VERSION 5.8 ;
BUSBITCHARS "[]" ;
DIVIDERCHAR "/" ;
UNITS
    DATABASE MICRONS 1000 ;
END UNITS

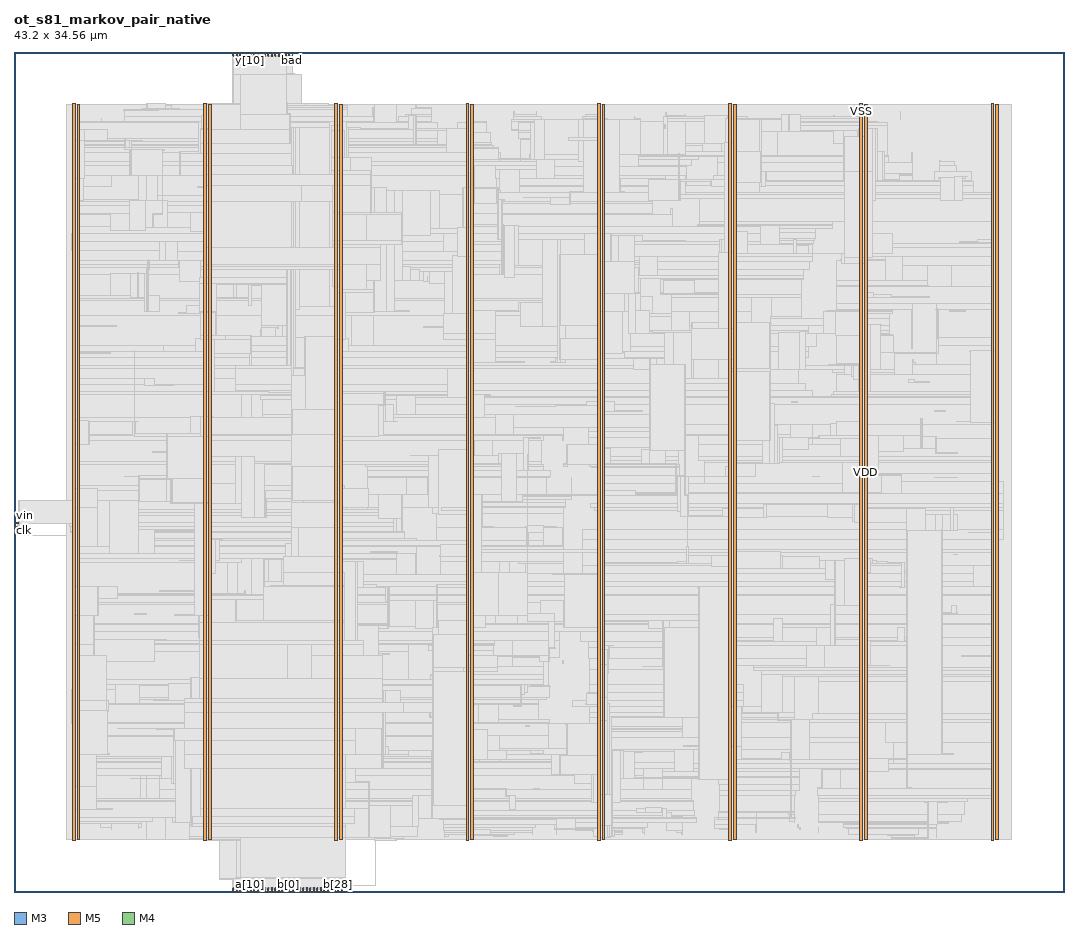
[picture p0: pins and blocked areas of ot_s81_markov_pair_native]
MACRO ot_s81_markov_pair_native
  FOREIGN ot_s81_markov_pair_native 0 0 ;
  CLASS BLOCK ;
  SIZE 43.2 BY 34.56 ;
  PIN a[0]
    DIRECTION INPUT ;
    USE SIGNAL ;
    PORT
      LAYER M3 ;
        RECT  9 0 9.018 0.144 ;
    END
  END a[0]
  PIN a[10]
    DIRECTION INPUT ;
    USE SIGNAL ;
    PORT
      LAYER M3 ;
        RECT  9.72 0 9.738 0.144 ;
    END
  END a[10]
  PIN a[11]
    DIRECTION INPUT ;
    USE SIGNAL ;
    PORT
      LAYER M5 ;
        RECT  9.744 0 9.768 0.192 ;
    END
  END a[11]
  PIN a[12]
    DIRECTION INPUT ;
    USE SIGNAL ;
    PORT
      LAYER M3 ;
        RECT  9.864 0 9.882 0.144 ;
    END
  END a[12]
  PIN a[13]
    DIRECTION INPUT ;
    USE SIGNAL ;
    PORT
      LAYER M5 ;
        RECT  9.888 0 9.912 0.192 ;
    END
  END a[13]
  PIN a[14]
    DIRECTION INPUT ;
    USE SIGNAL ;
    PORT
      LAYER M3 ;
        RECT  10.008 0 10.026 0.144 ;
    END
  END a[14]
  PIN a[15]
    DIRECTION INPUT ;
    USE SIGNAL ;
    PORT
      LAYER M5 ;
        RECT  10.032 0 10.056 0.192 ;
    END
  END a[15]
  PIN a[16]
    DIRECTION INPUT ;
    USE SIGNAL ;
    PORT
      LAYER M3 ;
        RECT  10.152 0 10.17 0.144 ;
    END
  END a[16]
  PIN a[17]
    DIRECTION INPUT ;
    USE SIGNAL ;
    PORT
      LAYER M5 ;
        RECT  10.176 0 10.2 0.192 ;
    END
  END a[17]
  PIN a[18]
    DIRECTION INPUT ;
    USE SIGNAL ;
    PORT
      LAYER M3 ;
        RECT  10.296 0 10.314 0.144 ;
    END
  END a[18]
  PIN a[19]
    DIRECTION INPUT ;
    USE SIGNAL ;
    PORT
      LAYER M5 ;
        RECT  10.32 0 10.344 0.192 ;
    END
  END a[19]
  PIN a[1]
    DIRECTION INPUT ;
    USE SIGNAL ;
    PORT
      LAYER M5 ;
        RECT  9.024 0 9.048 0.192 ;
    END
  END a[1]
  PIN a[20]
    DIRECTION INPUT ;
    USE SIGNAL ;
    PORT
      LAYER M3 ;
        RECT  10.44 0 10.458 0.144 ;
    END
  END a[20]
  PIN a[21]
    DIRECTION INPUT ;
    USE SIGNAL ;
    PORT
      LAYER M5 ;
        RECT  10.464 0 10.488 0.192 ;
    END
  END a[21]
  PIN a[22]
    DIRECTION INPUT ;
    USE SIGNAL ;
    PORT
      LAYER M3 ;
        RECT  10.584 0 10.602 0.144 ;
    END
  END a[22]
  PIN a[23]
    DIRECTION INPUT ;
    USE SIGNAL ;
    PORT
      LAYER M5 ;
        RECT  10.608 0 10.632 0.192 ;
    END
  END a[23]
  PIN a[24]
    DIRECTION INPUT ;
    USE SIGNAL ;
    PORT
      LAYER M3 ;
        RECT  10.728 0 10.746 0.144 ;
    END
  END a[24]
  PIN a[25]
    DIRECTION INPUT ;
    USE SIGNAL ;
    PORT
      LAYER M5 ;
        RECT  10.752 0 10.776 0.192 ;
    END
  END a[25]
  PIN a[26]
    DIRECTION INPUT ;
    USE SIGNAL ;
    PORT
      LAYER M3 ;
        RECT  10.872 0 10.89 0.144 ;
    END
  END a[26]
  PIN a[27]
    DIRECTION INPUT ;
    USE SIGNAL ;
    PORT
      LAYER M5 ;
        RECT  10.896 0 10.92 0.192 ;
    END
  END a[27]
  PIN a[28]
    DIRECTION INPUT ;
    USE SIGNAL ;
    PORT
      LAYER M3 ;
        RECT  11.016 0 11.034 0.144 ;
    END
  END a[28]
  PIN a[29]
    DIRECTION INPUT ;
    USE SIGNAL ;
    PORT
      LAYER M5 ;
        RECT  11.04 0 11.064 0.192 ;
    END
  END a[29]
  PIN a[2]
    DIRECTION INPUT ;
    USE SIGNAL ;
    PORT
      LAYER M3 ;
        RECT  9.144 0 9.162 0.144 ;
    END
  END a[2]
  PIN a[30]
    DIRECTION INPUT ;
    USE SIGNAL ;
    PORT
      LAYER M3 ;
        RECT  11.16 0 11.178 0.144 ;
    END
  END a[30]
  PIN a[31]
    DIRECTION INPUT ;
    USE SIGNAL ;
    PORT
      LAYER M5 ;
        RECT  11.184 0 11.208 0.192 ;
    END
  END a[31]
  PIN a[3]
    DIRECTION INPUT ;
    USE SIGNAL ;
    PORT
      LAYER M5 ;
        RECT  9.168 0 9.192 0.192 ;
    END
  END a[3]
  PIN a[4]
    DIRECTION INPUT ;
    USE SIGNAL ;
    PORT
      LAYER M3 ;
        RECT  9.288 0 9.306 0.144 ;
    END
  END a[4]
  PIN a[5]
    DIRECTION INPUT ;
    USE SIGNAL ;
    PORT
      LAYER M5 ;
        RECT  9.312 0 9.336 0.192 ;
    END
  END a[5]
  PIN a[6]
    DIRECTION INPUT ;
    USE SIGNAL ;
    PORT
      LAYER M3 ;
        RECT  9.432 0 9.45 0.144 ;
    END
  END a[6]
  PIN a[7]
    DIRECTION INPUT ;
    USE SIGNAL ;
    PORT
      LAYER M5 ;
        RECT  9.456 0 9.48 0.192 ;
    END
  END a[7]
  PIN a[8]
    DIRECTION INPUT ;
    USE SIGNAL ;
    PORT
      LAYER M3 ;
        RECT  9.576 0 9.594 0.144 ;
    END
  END a[8]
  PIN a[9]
    DIRECTION INPUT ;
    USE SIGNAL ;
    PORT
      LAYER M5 ;
        RECT  9.6 0 9.624 0.192 ;
    END
  END a[9]
  PIN b[0]
    DIRECTION INPUT ;
    USE SIGNAL ;
    PORT
      LAYER M3 ;
        RECT  11.304 0 11.322 0.144 ;
    END
  END b[0]
  PIN b[10]
    DIRECTION INPUT ;
    USE SIGNAL ;
    PORT
      LAYER M3 ;
        RECT  12.024 0 12.042 0.144 ;
    END
  END b[10]
  PIN b[11]
    DIRECTION INPUT ;
    USE SIGNAL ;
    PORT
      LAYER M5 ;
        RECT  12.048 0 12.072 0.192 ;
    END
  END b[11]
  PIN b[12]
    DIRECTION INPUT ;
    USE SIGNAL ;
    PORT
      LAYER M3 ;
        RECT  12.168 0 12.186 0.144 ;
    END
  END b[12]
  PIN b[13]
    DIRECTION INPUT ;
    USE SIGNAL ;
    PORT
      LAYER M5 ;
        RECT  12.192 0 12.216 0.192 ;
    END
  END b[13]
  PIN b[14]
    DIRECTION INPUT ;
    USE SIGNAL ;
    PORT
      LAYER M3 ;
        RECT  12.312 0 12.33 0.144 ;
    END
  END b[14]
  PIN b[15]
    DIRECTION INPUT ;
    USE SIGNAL ;
    PORT
      LAYER M5 ;
        RECT  12.336 0 12.36 0.192 ;
    END
  END b[15]
  PIN b[16]
    DIRECTION INPUT ;
    USE SIGNAL ;
    PORT
      LAYER M3 ;
        RECT  12.456 0 12.474 0.144 ;
    END
  END b[16]
  PIN b[17]
    DIRECTION INPUT ;
    USE SIGNAL ;
    PORT
      LAYER M5 ;
        RECT  12.48 0 12.504 0.192 ;
    END
  END b[17]
  PIN b[18]
    DIRECTION INPUT ;
    USE SIGNAL ;
    PORT
      LAYER M3 ;
        RECT  12.6 0 12.618 0.144 ;
    END
  END b[18]
  PIN b[19]
    DIRECTION INPUT ;
    USE SIGNAL ;
    PORT
      LAYER M5 ;
        RECT  12.624 0 12.648 0.192 ;
    END
  END b[19]
  PIN b[1]
    DIRECTION INPUT ;
    USE SIGNAL ;
    PORT
      LAYER M5 ;
        RECT  11.328 0 11.352 0.192 ;
    END
  END b[1]
  PIN b[20]
    DIRECTION INPUT ;
    USE SIGNAL ;
    PORT
      LAYER M3 ;
        RECT  12.744 0 12.762 0.144 ;
    END
  END b[20]
  PIN b[21]
    DIRECTION INPUT ;
    USE SIGNAL ;
    PORT
      LAYER M5 ;
        RECT  12.768 0 12.792 0.192 ;
    END
  END b[21]
  PIN b[22]
    DIRECTION INPUT ;
    USE SIGNAL ;
    PORT
      LAYER M3 ;
        RECT  12.888 0 12.906 0.144 ;
    END
  END b[22]
  PIN b[23]
    DIRECTION INPUT ;
    USE SIGNAL ;
    PORT
      LAYER M5 ;
        RECT  12.912 0 12.936 0.192 ;
    END
  END b[23]
  PIN b[24]
    DIRECTION INPUT ;
    USE SIGNAL ;
    PORT
      LAYER M3 ;
        RECT  13.032 0 13.05 0.144 ;
    END
  END b[24]
  PIN b[25]
    DIRECTION INPUT ;
    USE SIGNAL ;
    PORT
      LAYER M5 ;
        RECT  13.056 0 13.08 0.192 ;
    END
  END b[25]
  PIN b[26]
    DIRECTION INPUT ;
    USE SIGNAL ;
    PORT
      LAYER M3 ;
        RECT  13.176 0 13.194 0.144 ;
    END
  END b[26]
  PIN b[27]
    DIRECTION INPUT ;
    USE SIGNAL ;
    PORT
      LAYER M5 ;
        RECT  13.2 0 13.224 0.192 ;
    END
  END b[27]
  PIN b[28]
    DIRECTION INPUT ;
    USE SIGNAL ;
    PORT
      LAYER M3 ;
        RECT  13.32 0 13.338 0.144 ;
    END
  END b[28]
  PIN b[29]
    DIRECTION INPUT ;
    USE SIGNAL ;
    PORT
      LAYER M5 ;
        RECT  13.344 0 13.368 0.192 ;
    END
  END b[29]
  PIN b[2]
    DIRECTION INPUT ;
    USE SIGNAL ;
    PORT
      LAYER M3 ;
        RECT  11.448 0 11.466 0.144 ;
    END
  END b[2]
  PIN b[30]
    DIRECTION INPUT ;
    USE SIGNAL ;
    PORT
      LAYER M3 ;
        RECT  13.464 0 13.482 0.144 ;
    END
  END b[30]
  PIN b[31]
    DIRECTION INPUT ;
    USE SIGNAL ;
    PORT
      LAYER M5 ;
        RECT  13.488 0 13.512 0.192 ;
    END
  END b[31]
  PIN b[3]
    DIRECTION INPUT ;
    USE SIGNAL ;
    PORT
      LAYER M5 ;
        RECT  11.472 0 11.496 0.192 ;
    END
  END b[3]
  PIN b[4]
    DIRECTION INPUT ;
    USE SIGNAL ;
    PORT
      LAYER M3 ;
        RECT  11.592 0 11.61 0.144 ;
    END
  END b[4]
  PIN b[5]
    DIRECTION INPUT ;
    USE SIGNAL ;
    PORT
      LAYER M5 ;
        RECT  11.616 0 11.64 0.192 ;
    END
  END b[5]
  PIN b[6]
    DIRECTION INPUT ;
    USE SIGNAL ;
    PORT
      LAYER M3 ;
        RECT  11.736 0 11.754 0.144 ;
    END
  END b[6]
  PIN b[7]
    DIRECTION INPUT ;
    USE SIGNAL ;
    PORT
      LAYER M5 ;
        RECT  11.76 0 11.784 0.192 ;
    END
  END b[7]
  PIN b[8]
    DIRECTION INPUT ;
    USE SIGNAL ;
    PORT
      LAYER M3 ;
        RECT  11.88 0 11.898 0.144 ;
    END
  END b[8]
  PIN b[9]
    DIRECTION INPUT ;
    USE SIGNAL ;
    PORT
      LAYER M5 ;
        RECT  11.904 0 11.928 0.192 ;
    END
  END b[9]
  PIN bad
    DIRECTION OUTPUT ;
    USE SIGNAL ;
    PORT
      LAYER M3 ;
        RECT  11.448 34.416 11.466 34.56 ;
    END
  END bad
  PIN clk
    DIRECTION INPUT ;
    USE SIGNAL ;
    PORT
      LAYER M4 ;
        RECT  0 14.88 0.192 14.904 ;
    END
  END clk
  PIN rst_n
    DIRECTION INPUT ;
    USE SIGNAL ;
    PORT
      LAYER M4 ;
        RECT  0 15.024 0.192 15.048 ;
    END
  END rst_n
  PIN vin
    DIRECTION INPUT ;
    USE SIGNAL ;
    PORT
      LAYER M4 ;
        RECT  0 15.168 0.192 15.192 ;
    END
  END vin
  PIN vout
    DIRECTION OUTPUT ;
    USE SIGNAL ;
    PORT
      LAYER M3 ;
        RECT  11.304 34.416 11.322 34.56 ;
    END
  END vout
  PIN y[0]
    DIRECTION OUTPUT ;
    USE SIGNAL ;
    PORT
      LAYER M3 ;
        RECT  9 34.416 9.018 34.56 ;
    END
  END y[0]
  PIN y[10]
    DIRECTION OUTPUT ;
    USE SIGNAL ;
    PORT
      LAYER M3 ;
        RECT  9.72 34.416 9.738 34.56 ;
    END
  END y[10]
  PIN y[11]
    DIRECTION OUTPUT ;
    USE SIGNAL ;
    PORT
      LAYER M5 ;
        RECT  9.744 34.368 9.768 34.56 ;
    END
  END y[11]
  PIN y[12]
    DIRECTION OUTPUT ;
    USE SIGNAL ;
    PORT
      LAYER M3 ;
        RECT  9.864 34.416 9.882 34.56 ;
    END
  END y[12]
  PIN y[13]
    DIRECTION OUTPUT ;
    USE SIGNAL ;
    PORT
      LAYER M5 ;
        RECT  9.888 34.368 9.912 34.56 ;
    END
  END y[13]
  PIN y[14]
    DIRECTION OUTPUT ;
    USE SIGNAL ;
    PORT
      LAYER M3 ;
        RECT  10.008 34.416 10.026 34.56 ;
    END
  END y[14]
  PIN y[15]
    DIRECTION OUTPUT ;
    USE SIGNAL ;
    PORT
      LAYER M5 ;
        RECT  10.032 34.368 10.056 34.56 ;
    END
  END y[15]
  PIN y[16]
    DIRECTION OUTPUT ;
    USE SIGNAL ;
    PORT
      LAYER M3 ;
        RECT  10.152 34.416 10.17 34.56 ;
    END
  END y[16]
  PIN y[17]
    DIRECTION OUTPUT ;
    USE SIGNAL ;
    PORT
      LAYER M5 ;
        RECT  10.176 34.368 10.2 34.56 ;
    END
  END y[17]
  PIN y[18]
    DIRECTION OUTPUT ;
    USE SIGNAL ;
    PORT
      LAYER M3 ;
        RECT  10.296 34.416 10.314 34.56 ;
    END
  END y[18]
  PIN y[19]
    DIRECTION OUTPUT ;
    USE SIGNAL ;
    PORT
      LAYER M5 ;
        RECT  10.32 34.368 10.344 34.56 ;
    END
  END y[19]
  PIN y[1]
    DIRECTION OUTPUT ;
    USE SIGNAL ;
    PORT
      LAYER M5 ;
        RECT  9.024 34.368 9.048 34.56 ;
    END
  END y[1]
  PIN y[20]
    DIRECTION OUTPUT ;
    USE SIGNAL ;
    PORT
      LAYER M3 ;
        RECT  10.44 34.416 10.458 34.56 ;
    END
  END y[20]
  PIN y[21]
    DIRECTION OUTPUT ;
    USE SIGNAL ;
    PORT
      LAYER M5 ;
        RECT  10.464 34.368 10.488 34.56 ;
    END
  END y[21]
  PIN y[22]
    DIRECTION OUTPUT ;
    USE SIGNAL ;
    PORT
      LAYER M3 ;
        RECT  10.584 34.416 10.602 34.56 ;
    END
  END y[22]
  PIN y[23]
    DIRECTION OUTPUT ;
    USE SIGNAL ;
    PORT
      LAYER M5 ;
        RECT  10.608 34.368 10.632 34.56 ;
    END
  END y[23]
  PIN y[24]
    DIRECTION OUTPUT ;
    USE SIGNAL ;
    PORT
      LAYER M3 ;
        RECT  10.728 34.416 10.746 34.56 ;
    END
  END y[24]
  PIN y[25]
    DIRECTION OUTPUT ;
    USE SIGNAL ;
    PORT
      LAYER M5 ;
        RECT  10.752 34.368 10.776 34.56 ;
    END
  END y[25]
  PIN y[26]
    DIRECTION OUTPUT ;
    USE SIGNAL ;
    PORT
      LAYER M3 ;
        RECT  10.872 34.416 10.89 34.56 ;
    END
  END y[26]
  PIN y[27]
    DIRECTION OUTPUT ;
    USE SIGNAL ;
    PORT
      LAYER M5 ;
        RECT  10.896 34.368 10.92 34.56 ;
    END
  END y[27]
  PIN y[28]
    DIRECTION OUTPUT ;
    USE SIGNAL ;
    PORT
      LAYER M3 ;
        RECT  11.016 34.416 11.034 34.56 ;
    END
  END y[28]
  PIN y[29]
    DIRECTION OUTPUT ;
    USE SIGNAL ;
    PORT
      LAYER M5 ;
        RECT  11.04 34.368 11.064 34.56 ;
    END
  END y[29]
  PIN y[2]
    DIRECTION OUTPUT ;
    USE SIGNAL ;
    PORT
      LAYER M3 ;
        RECT  9.144 34.416 9.162 34.56 ;
    END
  END y[2]
  PIN y[30]
    DIRECTION OUTPUT ;
    USE SIGNAL ;
    PORT
      LAYER M3 ;
        RECT  11.16 34.416 11.178 34.56 ;
    END
  END y[30]
  PIN y[31]
    DIRECTION OUTPUT ;
    USE SIGNAL ;
    PORT
      LAYER M5 ;
        RECT  11.184 34.368 11.208 34.56 ;
    END
  END y[31]
  PIN y[3]
    DIRECTION OUTPUT ;
    USE SIGNAL ;
    PORT
      LAYER M5 ;
        RECT  9.168 34.368 9.192 34.56 ;
    END
  END y[3]
  PIN y[4]
    DIRECTION OUTPUT ;
    USE SIGNAL ;
    PORT
      LAYER M3 ;
        RECT  9.288 34.416 9.306 34.56 ;
    END
  END y[4]
  PIN y[5]
    DIRECTION OUTPUT ;
    USE SIGNAL ;
    PORT
      LAYER M5 ;
        RECT  9.312 34.368 9.336 34.56 ;
    END
  END y[5]
  PIN y[6]
    DIRECTION OUTPUT ;
    USE SIGNAL ;
    PORT
      LAYER M3 ;
        RECT  9.432 34.416 9.45 34.56 ;
    END
  END y[6]
  PIN y[7]
    DIRECTION OUTPUT ;
    USE SIGNAL ;
    PORT
      LAYER M5 ;
        RECT  9.456 34.368 9.48 34.56 ;
    END
  END y[7]
  PIN y[8]
    DIRECTION OUTPUT ;
    USE SIGNAL ;
    PORT
      LAYER M3 ;
        RECT  9.576 34.416 9.594 34.56 ;
    END
  END y[8]
  PIN y[9]
    DIRECTION OUTPUT ;
    USE SIGNAL ;
    PORT
      LAYER M5 ;
        RECT  9.6 34.368 9.624 34.56 ;
    END
  END y[9]
  PIN VDD
    DIRECTION INOUT ;
    USE POWER ;
    PORT
      LAYER M5 ;
        RECT  40.392 2.151 40.512 32.409 ;
        RECT  34.992 2.151 35.112 32.409 ;
        RECT  29.592 2.151 29.712 32.409 ;
        RECT  24.192 2.151 24.312 32.409 ;
        RECT  18.792 2.151 18.912 32.409 ;
        RECT  13.392 2.151 13.512 32.409 ;
        RECT  7.992 2.151 8.112 32.409 ;
        RECT  2.592 2.151 2.712 32.409 ;
    END
  END VDD
  PIN VSS
    DIRECTION INOUT ;
    USE GROUND ;
    PORT
      LAYER M5 ;
        RECT  40.2 2.137 40.32 32.423 ;
        RECT  34.8 2.137 34.92 32.423 ;
        RECT  29.4 2.137 29.52 32.423 ;
        RECT  24 2.137 24.12 32.423 ;
        RECT  18.6 2.137 18.72 32.423 ;
        RECT  13.2 2.137 13.32 32.423 ;
        RECT  7.8 2.137 7.92 32.423 ;
        RECT  2.4 2.137 2.52 32.423 ;
    END
  END VSS
  # OT_OBS_CLOSED layer=M5 d_um=1.536 added=67
  OBS
    LAYER RVTN ;
     RECT  2.16 2.16 41.04 2.295 ;
     RECT  2.16 2.565 41.04 2.835 ;
     RECT  2.16 3.105 41.04 3.375 ;
     RECT  2.16 3.645 41.04 3.915 ;
     RECT  2.16 4.185 41.04 4.455 ;
     RECT  2.16 4.725 41.04 4.995 ;
     RECT  2.16 5.265 41.04 5.535 ;
     RECT  2.16 5.805 41.04 6.075 ;
     RECT  2.16 6.345 41.04 6.615 ;
     RECT  2.16 6.885 41.04 7.155 ;
     RECT  2.16 7.425 41.04 7.695 ;
     RECT  2.16 7.965 41.04 8.235 ;
     RECT  2.16 8.505 41.04 8.775 ;
     RECT  2.16 9.045 41.04 9.315 ;
     RECT  2.16 9.585 41.04 9.855 ;
     RECT  2.16 10.125 41.04 10.395 ;
     RECT  2.16 10.665 41.04 10.935 ;
     RECT  2.16 11.205 41.04 11.475 ;
     RECT  2.16 11.745 41.04 12.015 ;
     RECT  2.16 12.285 41.04 12.555 ;
     RECT  2.16 12.825 41.04 13.095 ;
     RECT  2.16 13.365 41.04 13.635 ;
     RECT  2.16 13.905 41.04 14.175 ;
     RECT  2.16 14.445 41.04 14.715 ;
     RECT  2.16 14.985 41.04 15.255 ;
     RECT  2.16 15.525 41.04 15.795 ;
     RECT  2.16 16.065 41.04 16.335 ;
     RECT  2.16 16.605 41.04 16.875 ;
     RECT  2.16 17.145 41.04 17.415 ;
     RECT  2.16 17.685 41.04 17.955 ;
     RECT  2.16 18.225 41.04 18.495 ;
     RECT  2.16 18.765 41.04 19.035 ;
     RECT  2.16 19.305 41.04 19.575 ;
     RECT  2.16 19.845 41.04 20.115 ;
     RECT  2.16 20.385 41.04 20.655 ;
     RECT  2.16 20.925 41.04 21.195 ;
     RECT  2.16 21.465 41.04 21.735 ;
     RECT  2.16 22.005 41.04 22.275 ;
     RECT  2.16 22.545 41.04 22.815 ;
     RECT  2.16 23.085 41.04 23.355 ;
     RECT  2.16 23.625 41.04 23.895 ;
     RECT  2.16 24.165 41.04 24.435 ;
     RECT  2.16 24.705 41.04 24.975 ;
     RECT  2.16 25.245 41.04 25.515 ;
     RECT  2.16 25.785 41.04 26.055 ;
     RECT  2.16 26.325 41.04 26.595 ;
     RECT  2.16 26.865 41.04 27.135 ;
     RECT  2.16 27.405 41.04 27.675 ;
     RECT  2.16 27.945 41.04 28.215 ;
     RECT  2.16 28.485 41.04 28.755 ;
     RECT  2.16 29.025 41.04 29.295 ;
     RECT  2.16 29.565 41.04 29.835 ;
     RECT  2.16 30.105 41.04 30.375 ;
     RECT  2.16 30.645 41.04 30.915 ;
     RECT  2.16 31.185 41.04 31.455 ;
     RECT  2.16 31.725 41.04 31.995 ;
     RECT  2.16 32.265 41.04 32.4 ;
    LAYER RVTP ;
     RECT  2.16 2.295 41.04 2.565 ;
     RECT  2.16 2.835 41.04 3.105 ;
     RECT  2.16 3.375 41.04 3.645 ;
     RECT  2.16 3.915 41.04 4.185 ;
     RECT  2.16 4.455 41.04 4.725 ;
     RECT  2.16 4.995 41.04 5.265 ;
     RECT  2.16 5.535 41.04 5.805 ;
     RECT  2.16 6.075 41.04 6.345 ;
     RECT  2.16 6.615 41.04 6.885 ;
     RECT  2.16 7.155 41.04 7.425 ;
     RECT  2.16 7.695 41.04 7.965 ;
     RECT  2.16 8.235 41.04 8.505 ;
     RECT  2.16 8.775 41.04 9.045 ;
     RECT  2.16 9.315 41.04 9.585 ;
     RECT  2.16 9.855 41.04 10.125 ;
     RECT  2.16 10.395 41.04 10.665 ;
     RECT  2.16 10.935 41.04 11.205 ;
     RECT  2.16 11.475 41.04 11.745 ;
     RECT  2.16 12.015 41.04 12.285 ;
     RECT  2.16 12.555 41.04 12.825 ;
     RECT  2.16 13.095 41.04 13.365 ;
     RECT  2.16 13.635 41.04 13.905 ;
     RECT  2.16 14.175 41.04 14.445 ;
     RECT  2.16 14.715 41.04 14.985 ;
     RECT  2.16 15.255 41.04 15.525 ;
     RECT  2.16 15.795 41.04 16.065 ;
     RECT  2.16 16.335 41.04 16.605 ;
     RECT  2.16 16.875 41.04 17.145 ;
     RECT  2.16 17.415 41.04 17.685 ;
     RECT  2.16 17.955 41.04 18.225 ;
     RECT  2.16 18.495 41.04 18.765 ;
     RECT  2.16 19.035 41.04 19.305 ;
     RECT  2.16 19.575 41.04 19.845 ;
     RECT  2.16 20.115 41.04 20.385 ;
     RECT  2.16 20.655 41.04 20.925 ;
     RECT  2.16 21.195 41.04 21.465 ;
     RECT  2.16 21.735 41.04 22.005 ;
     RECT  2.16 22.275 41.04 22.545 ;
     RECT  2.16 22.815 41.04 23.085 ;
     RECT  2.16 23.355 41.04 23.625 ;
     RECT  2.16 23.895 41.04 24.165 ;
     RECT  2.16 24.435 41.04 24.705 ;
     RECT  2.16 24.975 41.04 25.245 ;
     RECT  2.16 25.515 41.04 25.785 ;
     RECT  2.16 26.055 41.04 26.325 ;
     RECT  2.16 26.595 41.04 26.865 ;
     RECT  2.16 27.135 41.04 27.405 ;
     RECT  2.16 27.675 41.04 27.945 ;
     RECT  2.16 28.215 41.04 28.485 ;
     RECT  2.16 28.755 41.04 29.025 ;
     RECT  2.16 29.295 41.04 29.565 ;
     RECT  2.16 29.835 41.04 30.105 ;
     RECT  2.16 30.375 41.04 30.645 ;
     RECT  2.16 30.915 41.04 31.185 ;
     RECT  2.16 31.455 41.04 31.725 ;
     RECT  2.16 31.995 41.04 32.265 ;
    LAYER M1 ;
     RECT  2.16 2.151 41.04 32.409 ;
    LAYER M2 ;
     RECT  0.211 14.652 2.16 14.67 ;
     RECT  2.16 2.151 5.467 32.409 ;
     RECT  5.467 2.151 6.251 32.454 ;
     RECT  6.251 2.151 8.203 32.409 ;
     RECT  8.203 2.151 9.203 32.454 ;
     RECT  9.203 2.151 9.211 32.409 ;
     RECT  9.427 33.741 9.671 33.759 ;
     RECT  9.211 2.034 9.751 32.409 ;
     RECT  9.571 0.144 9.923 0.162 ;
     RECT  9.751 1.998 10.247 32.409 ;
     RECT  10.247 2.034 10.463 32.409 ;
     RECT  10.463 2.151 11.011 32.409 ;
     RECT  10.867 33.624 11.155 33.642 ;
     RECT  11.011 2.151 11.299 32.454 ;
     RECT  11.155 33.624 11.299 33.678 ;
     RECT  11.299 2.151 11.507 33.678 ;
     RECT  11.507 2.151 11.687 33.642 ;
     RECT  11.623 0.144 11.759 0.162 ;
     RECT  11.687 33.624 11.831 33.642 ;
     RECT  11.687 2.151 12.947 32.454 ;
     RECT  12.739 0.144 13.027 0.162 ;
     RECT  13.027 0.144 13.171 0.234 ;
     RECT  12.947 2.151 13.171 32.409 ;
     RECT  13.171 1.728 13.343 32.409 ;
     RECT  13.171 0.144 13.559 0.279 ;
     RECT  13.559 0.216 13.631 0.279 ;
     RECT  13.343 2.151 14.827 32.409 ;
     RECT  13.631 0.261 14.891 0.279 ;
     RECT  14.827 2.106 15.719 32.409 ;
     RECT  15.719 2.151 41.04 32.409 ;
    LAYER M3 ;
     RECT  9 0.108 13.482 0.139 ;
     RECT  9 0.139 13.554 0.211 ;
     RECT  9 0.211 13.626 0.523 ;
     RECT  14.868 0.256 14.886 2.101 ;
     RECT  8.46 0.523 13.626 2.143 ;
     RECT  7.815 2.143 13.626 2.191 ;
     RECT  14.832 2.101 15.714 2.191 ;
     RECT  36.108 2.191 36.126 2.203 ;
     RECT  24.015 2.143 24.105 2.227 ;
     RECT  36.108 2.203 36.306 2.227 ;
     RECT  37.044 2.191 37.062 2.227 ;
     RECT  7.2 2.191 13.626 2.263 ;
     RECT  14.832 2.191 16.038 2.263 ;
     RECT  24.012 2.227 24.534 2.293 ;
     RECT  17.712 2.227 17.73 2.299 ;
     RECT  20.16 2.263 20.178 2.299 ;
     RECT  23.868 2.293 24.534 2.299 ;
     RECT  18.615 2.143 18.705 2.335 ;
     RECT  19.728 2.299 20.322 2.335 ;
     RECT  36.108 2.227 37.062 2.335 ;
     RECT  18.615 2.335 20.322 2.347 ;
     RECT  34.815 2.143 34.905 2.347 ;
     RECT  17.712 2.299 17.874 2.371 ;
     RECT  18.615 2.347 20.574 2.371 ;
     RECT  23.868 2.299 24.714 2.371 ;
     RECT  34.344 2.347 34.905 2.371 ;
     RECT  35.928 2.335 37.062 2.371 ;
     RECT  2.415 2.143 2.505 2.413 ;
     RECT  29.415 2.143 29.505 2.413 ;
     RECT  40.215 2.143 40.305 2.413 ;
     RECT  17.712 2.371 20.574 2.461 ;
     RECT  21.312 2.371 21.33 2.461 ;
     RECT  23.868 2.371 25.038 2.461 ;
     RECT  25.92 2.371 25.938 2.461 ;
     RECT  27.468 2.371 27.486 2.461 ;
     RECT  23.832 2.461 25.038 2.491 ;
     RECT  17.712 2.461 21.33 2.533 ;
     RECT  23.796 2.491 25.038 2.533 ;
     RECT  27.252 2.461 27.486 2.533 ;
     RECT  29.415 2.413 29.697 2.569 ;
     RECT  22.32 2.371 22.338 2.587 ;
     RECT  23.112 2.533 25.038 2.605 ;
     RECT  25.848 2.461 25.938 2.605 ;
     RECT  29.016 2.569 29.697 2.605 ;
     RECT  34.344 2.371 37.206 2.605 ;
     RECT  37.944 2.227 37.962 2.605 ;
     RECT  3.996 2.569 4.014 2.641 ;
     RECT  5.112 2.605 5.13 2.641 ;
     RECT  17.676 2.533 21.33 2.641 ;
     RECT  23.112 2.605 25.938 2.641 ;
     RECT  32.328 2.569 32.346 2.641 ;
     RECT  34.272 2.605 37.962 2.641 ;
     RECT  32.256 2.641 32.346 2.669 ;
     RECT  33.084 2.461 33.102 2.669 ;
     RECT  7.2 2.263 16.614 2.683 ;
     RECT  7.2 2.683 16.65 2.759 ;
     RECT  32.256 2.669 32.274 2.759 ;
     RECT  17.676 2.641 21.474 2.767 ;
     RECT  22.248 2.587 22.338 2.767 ;
     RECT  28.836 2.605 29.697 2.767 ;
     RECT  30.528 2.461 30.546 2.767 ;
     RECT  34.128 2.641 37.962 2.767 ;
     RECT  2.415 2.413 2.697 2.803 ;
     RECT  3.564 2.641 4.014 2.803 ;
     RECT  5.112 2.641 5.238 2.803 ;
     RECT  34.128 2.767 37.998 2.803 ;
     RECT  23.112 2.641 26.046 2.839 ;
     RECT  26.856 2.533 27.486 2.839 ;
     RECT  7.2 2.759 16.506 2.875 ;
     RECT  34.128 2.803 38.466 2.875 ;
     RECT  2.415 2.803 5.238 2.911 ;
     RECT  32.112 2.875 32.13 2.911 ;
     RECT  33.12 2.875 38.466 2.911 ;
     RECT  17.676 2.767 22.338 3.001 ;
     RECT  17.496 3.001 22.338 3.037 ;
     RECT  23.112 2.839 28.062 3.037 ;
     RECT  17.496 3.037 28.062 3.065 ;
     RECT  28.836 2.767 30.546 3.065 ;
     RECT  2.415 2.911 5.706 3.073 ;
     RECT  6.516 2.875 16.506 3.073 ;
     RECT  17.496 3.065 27.99 3.145 ;
     RECT  31.896 2.911 32.13 3.181 ;
     RECT  33.12 2.911 38.97 3.181 ;
     RECT  28.98 3.065 30.546 3.271 ;
     RECT  31.86 3.181 32.13 3.271 ;
     RECT  28.98 3.271 32.13 3.299 ;
     RECT  17.352 3.145 27.99 3.371 ;
     RECT  2.415 3.073 16.506 3.721 ;
     RECT  17.352 3.371 27.954 3.721 ;
     RECT  33.12 3.181 39.114 3.721 ;
     RECT  2.415 3.721 27.954 3.749 ;
     RECT  2.415 3.749 27.882 3.839 ;
     RECT  33.084 3.721 39.222 3.847 ;
     RECT  40.215 2.413 40.497 3.847 ;
     RECT  29.016 3.299 32.13 3.955 ;
     RECT  33.084 3.847 40.497 3.955 ;
     RECT  29.016 3.955 32.166 4.189 ;
     RECT  5.976 3.839 27.882 4.217 ;
     RECT  33.048 3.955 40.497 4.253 ;
     RECT  33.048 4.253 33.246 4.289 ;
     RECT  29.016 4.189 32.31 4.423 ;
     RECT  28.98 4.423 32.31 4.693 ;
     RECT  26.676 4.217 27.882 4.729 ;
     RECT  26.676 4.729 27.954 4.765 ;
     RECT  28.8 4.693 32.31 4.765 ;
     RECT  2.415 3.839 5.202 4.801 ;
     RECT  5.976 4.217 25.902 4.801 ;
     RECT  26.676 4.765 32.31 4.955 ;
     RECT  33.228 4.289 33.246 5.035 ;
     RECT  34.02 4.253 40.497 5.035 ;
     RECT  2.415 4.801 25.902 5.071 ;
     RECT  26.676 4.955 27.162 5.071 ;
     RECT  27.936 4.955 32.31 5.071 ;
     RECT  33.228 5.035 40.497 5.071 ;
     RECT  27.936 5.071 40.497 5.297 ;
     RECT  2.415 5.071 27.162 5.333 ;
     RECT  2.415 5.333 22.986 5.369 ;
     RECT  19.98 5.369 22.986 5.459 ;
     RECT  2.415 5.369 19.17 5.501 ;
     RECT  2.415 5.501 19.026 5.567 ;
     RECT  19.98 5.459 22.95 5.645 ;
     RECT  23.868 5.333 27.162 5.789 ;
     RECT  23.904 5.789 27.162 5.881 ;
     RECT  27.936 5.297 35.097 5.881 ;
     RECT  19.98 5.645 22.914 5.909 ;
     RECT  36.18 5.297 40.497 6.151 ;
     RECT  23.904 5.881 35.097 6.341 ;
     RECT  2.415 5.567 18.99 6.385 ;
     RECT  2.415 6.385 19.062 6.421 ;
     RECT  19.98 5.909 21.978 6.421 ;
     RECT  23.904 6.341 27.522 6.583 ;
     RECT  22.716 5.909 22.914 6.667 ;
     RECT  23.76 6.583 27.522 6.667 ;
     RECT  22.716 6.667 27.522 6.719 ;
     RECT  22.716 6.719 22.878 6.809 ;
     RECT  23.652 6.719 27.522 6.809 ;
     RECT  2.415 6.421 21.978 6.925 ;
     RECT  22.716 6.809 22.734 6.925 ;
     RECT  2.376 6.925 22.734 6.953 ;
     RECT  28.296 6.341 35.097 6.961 ;
     RECT  35.856 6.151 40.497 6.961 ;
     RECT  2.376 6.953 22.05 6.989 ;
     RECT  19.944 6.989 22.05 7.079 ;
     RECT  28.296 6.961 40.497 7.087 ;
     RECT  19.944 7.079 21.834 7.115 ;
     RECT  28.26 7.087 40.497 7.115 ;
     RECT  23.688 6.809 27.522 7.159 ;
     RECT  28.26 7.115 32.13 7.159 ;
     RECT  32.868 7.115 40.497 7.349 ;
     RECT  23.688 7.159 32.13 7.373 ;
     RECT  23.688 7.373 30.762 7.619 ;
     RECT  23.688 7.619 30.006 7.627 ;
     RECT  2.376 6.989 19.098 7.723 ;
     RECT  19.944 7.115 21.582 7.723 ;
     RECT  2.376 7.723 21.582 7.763 ;
     RECT  22.968 7.627 30.006 7.889 ;
     RECT  5.148 7.763 21.582 7.933 ;
     RECT  5.148 7.933 21.906 8.005 ;
     RECT  23.58 7.889 30.006 8.189 ;
     RECT  2.376 7.763 4.158 8.339 ;
     RECT  5.148 8.005 22.014 8.477 ;
     RECT  23.688 8.189 30.006 8.537 ;
     RECT  2.415 8.339 4.158 8.545 ;
     RECT  5.148 8.477 21.798 8.545 ;
     RECT  33.12 7.349 40.497 8.671 ;
     RECT  2.415 8.545 21.798 8.735 ;
     RECT  31.608 7.373 32.13 8.851 ;
     RECT  33.084 8.671 40.497 8.851 ;
     RECT  30.744 7.619 30.762 8.941 ;
     RECT  31.608 8.851 40.497 8.941 ;
     RECT  17.136 8.735 21.798 8.969 ;
     RECT  30.744 8.941 40.497 9.121 ;
     RECT  23.688 8.537 29.697 9.149 ;
     RECT  30.42 9.121 40.497 9.239 ;
     RECT  17.208 8.969 21.798 9.275 ;
     RECT  27.864 9.149 29.697 9.319 ;
     RECT  30.42 9.239 32.598 9.319 ;
     RECT  22.572 9.391 22.59 9.509 ;
     RECT  23.688 9.149 27.09 9.589 ;
     RECT  27.864 9.319 32.598 9.617 ;
     RECT  20.52 9.275 21.798 9.661 ;
     RECT  2.415 8.735 16.218 9.895 ;
     RECT  17.208 9.275 19.746 9.931 ;
     RECT  23.652 9.589 27.09 10.049 ;
     RECT  28.476 9.617 32.598 10.123 ;
     RECT  33.336 9.239 40.497 10.123 ;
     RECT  17.064 9.931 19.746 10.129 ;
     RECT  2.412 9.895 16.218 10.201 ;
     RECT  17.064 10.129 19.782 10.201 ;
     RECT  2.412 10.201 19.782 10.205 ;
     RECT  23.652 10.049 26.73 10.291 ;
     RECT  2.415 10.205 19.782 10.327 ;
     RECT  20.52 9.661 22.446 10.327 ;
     RECT  27.648 10.201 27.666 10.471 ;
     RECT  28.476 10.123 40.497 10.471 ;
     RECT  2.415 10.327 22.446 10.705 ;
     RECT  23.328 10.291 26.73 10.705 ;
     RECT  2.415 10.705 26.73 11.011 ;
     RECT  27.648 10.471 40.497 11.011 ;
     RECT  2.415 11.011 40.497 11.039 ;
     RECT  20.7 11.039 40.497 11.399 ;
     RECT  2.415 11.039 19.818 11.821 ;
     RECT  2.415 11.821 19.89 11.911 ;
     RECT  20.7 11.399 22.662 11.911 ;
     RECT  2.415 11.911 22.662 12.181 ;
     RECT  23.4 11.399 40.497 12.181 ;
     RECT  2.415 12.181 40.497 12.245 ;
     RECT  2.415 12.245 9.522 12.281 ;
     RECT  9.504 12.281 9.522 12.389 ;
     RECT  10.296 12.245 40.497 12.551 ;
     RECT  10.296 12.551 39.474 12.785 ;
     RECT  11.196 12.785 19.962 13.055 ;
     RECT  21.024 12.785 39.474 13.085 ;
     RECT  23.4 13.085 39.474 13.441 ;
     RECT  40.215 12.551 40.497 13.441 ;
     RECT  21.024 13.085 22.59 13.531 ;
     RECT  2.415 12.281 8.766 13.567 ;
     RECT  17.532 13.055 19.962 13.579 ;
     RECT  20.736 13.531 22.59 13.579 ;
     RECT  10.296 12.785 10.458 13.675 ;
     RECT  11.196 13.055 15.75 13.675 ;
     RECT  2.415 13.567 9.378 13.711 ;
     RECT  10.296 13.675 15.75 13.711 ;
     RECT  2.415 13.711 15.75 13.909 ;
     RECT  16.524 13.055 16.542 13.909 ;
     RECT  17.532 13.579 22.59 13.981 ;
     RECT  23.4 13.441 40.497 13.981 ;
     RECT  17.532 13.981 40.497 14.099 ;
     RECT  2.415 13.909 16.542 14.215 ;
     RECT  17.532 14.099 22.59 14.215 ;
     RECT  2.415 14.215 22.59 14.243 ;
     RECT  2.415 14.243 21.798 14.477 ;
     RECT  23.4 14.099 40.497 14.521 ;
     RECT  2.415 14.477 16.542 14.549 ;
     RECT  2.415 14.549 16.074 14.791 ;
     RECT  2.304 14.791 16.074 14.813 ;
     RECT  23.4 14.521 40.698 14.909 ;
     RECT  17.388 14.477 21.798 15.002 ;
     RECT  22.572 14.243 22.59 15.002 ;
     RECT  2.304 14.813 15.606 15.025 ;
     RECT  0.216 14.647 0.234 15.053 ;
     RECT  2.268 15.025 15.606 15.197 ;
     RECT  2.304 15.197 15.606 15.485 ;
     RECT  17.388 15.002 22.59 15.565 ;
     RECT  2.415 15.485 15.606 15.601 ;
     RECT  24.015 14.909 40.698 15.691 ;
     RECT  2.415 15.601 15.858 15.719 ;
     RECT  14.544 15.719 15.858 15.835 ;
     RECT  17.208 15.565 22.59 15.835 ;
     RECT  23.868 15.691 40.698 15.835 ;
     RECT  17.208 15.835 22.698 15.871 ;
     RECT  23.724 15.835 40.698 15.989 ;
     RECT  17.136 15.871 22.698 16.033 ;
     RECT  17.064 16.033 22.698 16.141 ;
     RECT  16.992 16.141 22.95 16.259 ;
     RECT  16.992 16.259 21.978 16.295 ;
     RECT  24.015 15.989 40.698 16.403 ;
     RECT  24.015 16.403 35.694 16.439 ;
     RECT  2.415 15.719 13.662 16.529 ;
     RECT  2.415 16.529 13.59 16.709 ;
     RECT  24.015 16.439 34.074 16.799 ;
     RECT  36.504 16.403 40.698 16.871 ;
     RECT  14.544 15.835 16.146 17.041 ;
     RECT  16.992 16.295 21.906 17.041 ;
     RECT  22.932 16.259 22.95 17.069 ;
     RECT  14.544 17.041 22.014 17.077 ;
     RECT  24.015 16.799 27.594 17.117 ;
     RECT  34.815 16.439 35.694 17.221 ;
     RECT  36.504 16.871 40.497 17.221 ;
     RECT  14.544 17.077 22.086 17.339 ;
     RECT  24.015 17.117 27.378 17.455 ;
     RECT  14.544 17.339 21.798 17.491 ;
     RECT  23.76 17.455 27.378 17.491 ;
     RECT  2.415 16.709 13.497 17.581 ;
     RECT  14.472 17.491 21.798 17.581 ;
     RECT  2.415 17.581 21.798 17.609 ;
     RECT  22.608 17.491 22.77 17.609 ;
     RECT  23.688 17.491 27.378 17.609 ;
     RECT  22.608 17.609 22.626 17.645 ;
     RECT  28.404 16.799 34.074 17.659 ;
     RECT  34.815 17.221 40.497 17.659 ;
     RECT  2.415 17.609 21.69 17.717 ;
     RECT  23.688 17.609 27.342 17.761 ;
     RECT  28.404 17.659 40.497 17.761 ;
     RECT  23.616 17.761 27.342 17.915 ;
     RECT  28.152 17.761 40.497 17.915 ;
     RECT  23.652 17.915 27.342 18.293 ;
     RECT  28.152 17.915 34.002 18.419 ;
     RECT  2.415 17.717 18.954 18.571 ;
     RECT  19.692 17.717 21.69 18.571 ;
     RECT  32.832 18.419 34.002 18.661 ;
     RECT  34.776 17.915 40.497 18.661 ;
     RECT  23.652 18.293 26.874 18.689 ;
     RECT  2.415 18.571 21.798 18.769 ;
     RECT  22.572 18.571 22.59 18.769 ;
     RECT  2.415 18.769 22.59 18.833 ;
     RECT  28.152 18.419 31.95 18.841 ;
     RECT  23.652 18.689 26.838 18.959 ;
     RECT  20.556 18.833 22.59 19.111 ;
     RECT  23.652 18.959 26.802 19.111 ;
     RECT  27.648 18.841 31.95 19.237 ;
     RECT  32.832 18.661 40.497 19.237 ;
     RECT  2.415 18.833 19.818 19.535 ;
     RECT  10.224 19.535 19.818 19.643 ;
     RECT  16.524 19.643 19.818 19.651 ;
     RECT  20.556 19.111 26.802 19.651 ;
     RECT  16.524 19.651 26.802 20.047 ;
     RECT  27.648 19.237 40.497 20.047 ;
     RECT  10.224 19.643 15.75 20.281 ;
     RECT  16.524 20.047 40.497 20.345 ;
     RECT  18.615 20.345 40.497 20.381 ;
     RECT  10.152 20.281 15.75 20.425 ;
     RECT  16.524 20.345 17.838 20.425 ;
     RECT  33.624 20.381 40.497 20.453 ;
     RECT  2.415 19.535 9.378 20.461 ;
     RECT  10.152 20.425 17.838 20.461 ;
     RECT  33.732 20.453 40.497 20.579 ;
     RECT  2.415 20.461 17.838 20.587 ;
     RECT  18.615 20.381 32.85 20.615 ;
     RECT  2.412 20.587 17.838 20.885 ;
     RECT  18.615 20.615 32.562 20.921 ;
     RECT  33.84 20.579 40.497 21.299 ;
     RECT  33.84 21.299 36.234 21.361 ;
     RECT  2.415 20.885 17.838 21.541 ;
     RECT  18.615 20.921 32.274 21.541 ;
     RECT  2.415 21.541 32.274 21.643 ;
     RECT  33.66 21.361 36.234 21.643 ;
     RECT  33.516 21.643 36.234 21.695 ;
     RECT  36.972 21.299 40.497 21.695 ;
     RECT  33.84 21.695 36.234 21.731 ;
     RECT  36.972 21.695 37.098 21.803 ;
     RECT  36.972 21.803 36.99 21.929 ;
     RECT  2.415 21.643 32.562 21.973 ;
     RECT  2.415 21.973 32.67 22.235 ;
     RECT  25.344 22.235 32.67 22.441 ;
     RECT  2.415 22.235 24.297 22.469 ;
     RECT  37.944 21.695 40.497 22.469 ;
     RECT  38.016 22.469 40.497 22.829 ;
     RECT  33.84 21.731 36.198 22.883 ;
     RECT  33.84 22.883 36.126 22.885 ;
     RECT  33.804 22.885 36.126 22.919 ;
     RECT  25.344 22.441 33.03 22.981 ;
     RECT  33.804 22.919 36.018 22.981 ;
     RECT  25.344 22.981 36.018 22.987 ;
     RECT  25.308 22.987 36.018 23.117 ;
     RECT  27.792 23.117 36.018 23.315 ;
     RECT  31.14 23.315 36.018 23.585 ;
     RECT  25.308 23.117 27.054 23.693 ;
     RECT  31.14 23.585 32.382 23.693 ;
     RECT  2.415 22.469 13.878 23.701 ;
     RECT  14.796 22.469 24.297 23.701 ;
     RECT  33.3 23.585 36.018 23.791 ;
     RECT  25.776 23.693 27.054 23.819 ;
     RECT  27.036 23.819 27.054 23.863 ;
     RECT  27.792 23.315 30.33 23.863 ;
     RECT  33.3 23.791 36.162 23.885 ;
     RECT  33.408 23.885 36.162 23.927 ;
     RECT  38.052 22.829 40.497 23.947 ;
     RECT  33.84 23.927 36.162 23.971 ;
     RECT  36.936 22.351 36.954 23.971 ;
     RECT  33.84 23.971 36.954 24.205 ;
     RECT  37.944 23.947 40.497 24.205 ;
     RECT  2.415 23.701 24.297 24.331 ;
     RECT  25.02 23.863 25.038 24.331 ;
     RECT  2.415 24.331 25.038 24.431 ;
     RECT  27.036 23.863 30.33 24.475 ;
     RECT  31.176 23.693 32.382 24.475 ;
     RECT  25.776 23.819 26.262 24.503 ;
     RECT  27.036 24.475 32.382 24.601 ;
     RECT  25.776 24.503 25.794 24.619 ;
     RECT  25.56 24.619 25.794 24.665 ;
     RECT  33.84 24.205 40.497 24.899 ;
     RECT  33.84 24.899 37.638 24.935 ;
     RECT  33.84 24.935 37.602 25.169 ;
     RECT  26.604 24.601 32.382 25.213 ;
     RECT  25.704 24.665 25.794 25.249 ;
     RECT  26.604 25.213 32.49 25.249 ;
     RECT  25.704 25.249 32.49 25.349 ;
     RECT  2.415 24.431 24.786 25.387 ;
     RECT  26.496 25.349 32.49 25.591 ;
     RECT  2.415 25.387 24.858 25.681 ;
     RECT  25.704 25.349 25.722 25.681 ;
     RECT  36.576 25.169 37.602 25.789 ;
     RECT  38.556 24.899 40.497 25.789 ;
     RECT  2.415 25.681 25.722 25.817 ;
     RECT  21.348 25.817 25.722 25.889 ;
     RECT  26.496 25.591 32.742 25.951 ;
     RECT  2.415 25.817 20.538 25.979 ;
     RECT  21.672 25.889 25.722 25.979 ;
     RECT  33.84 25.169 35.838 25.979 ;
     RECT  34.02 25.979 35.838 26.015 ;
     RECT  23.472 25.979 25.722 26.131 ;
     RECT  26.496 25.951 32.85 26.131 ;
     RECT  34.2 26.015 35.838 26.131 ;
     RECT  36.576 25.789 40.497 26.131 ;
     RECT  6.732 25.979 20.538 26.357 ;
     RECT  2.415 25.979 5.994 26.401 ;
     RECT  34.2 26.131 40.497 26.519 ;
     RECT  23.472 26.131 32.85 26.627 ;
     RECT  18.468 26.357 20.538 26.635 ;
     RECT  21.672 25.979 22.734 26.635 ;
     RECT  34.38 26.519 40.497 26.663 ;
     RECT  31.5 26.627 32.85 26.671 ;
     RECT  2.376 26.401 5.994 26.761 ;
     RECT  6.732 26.357 17.658 26.761 ;
     RECT  18.468 26.635 22.734 26.761 ;
     RECT  23.472 26.627 30.726 26.761 ;
     RECT  31.5 26.671 32.886 26.797 ;
     RECT  31.5 26.797 32.922 26.905 ;
     RECT  2.376 26.761 17.658 27.095 ;
     RECT  2.415 27.095 17.658 27.103 ;
     RECT  18.468 26.761 30.726 27.103 ;
     RECT  31.5 26.905 32.958 27.139 ;
     RECT  31.5 27.139 32.994 27.301 ;
     RECT  2.415 27.103 30.726 27.365 ;
     RECT  28.116 27.365 30.726 27.409 ;
     RECT  31.5 27.301 33.678 27.409 ;
     RECT  28.116 27.409 33.678 27.473 ;
     RECT  28.188 27.473 33.678 27.571 ;
     RECT  34.416 26.663 40.497 27.571 ;
     RECT  2.415 27.365 27.09 27.869 ;
     RECT  2.415 27.869 26.262 27.905 ;
     RECT  27 27.869 27.09 28.139 ;
     RECT  2.415 27.905 17.658 28.255 ;
     RECT  18.615 27.905 26.262 28.319 ;
     RECT  2.412 28.255 17.658 28.409 ;
     RECT  19.836 28.319 26.262 28.409 ;
     RECT  2.412 28.409 5.13 28.493 ;
     RECT  27.396 28.459 27.414 28.525 ;
     RECT  28.188 27.571 40.497 28.525 ;
     RECT  5.904 28.409 17.658 28.651 ;
     RECT  18.615 28.319 18.954 28.651 ;
     RECT  27.396 28.525 40.497 28.715 ;
     RECT  19.872 28.409 26.262 28.787 ;
     RECT  27.648 28.715 40.497 28.787 ;
     RECT  19.872 28.787 20.034 28.859 ;
     RECT  20.808 28.787 26.262 29.029 ;
     RECT  27.648 28.787 39.474 29.057 ;
     RECT  20.808 29.029 26.55 29.065 ;
     RECT  28.656 29.057 39.474 29.219 ;
     RECT  28.656 29.219 39.402 29.261 ;
     RECT  28.764 29.261 39.402 29.291 ;
     RECT  20.808 29.065 26.802 29.363 ;
     RECT  19.872 28.859 19.962 29.371 ;
     RECT  2.415 28.493 5.13 29.461 ;
     RECT  5.904 28.651 18.954 29.461 ;
     RECT  28.764 29.291 36.954 29.489 ;
     RECT  22.248 29.363 26.802 29.497 ;
     RECT  27.648 29.057 27.666 29.497 ;
     RECT  37.872 29.291 39.402 29.633 ;
     RECT  19.8 29.371 19.962 29.731 ;
     RECT  20.808 29.363 21.51 29.731 ;
     RECT  22.248 29.497 27.666 29.831 ;
     RECT  2.415 29.461 18.954 29.875 ;
     RECT  19.8 29.731 21.51 29.875 ;
     RECT  25.704 29.831 27.666 29.875 ;
     RECT  38.088 29.633 38.79 29.903 ;
     RECT  28.944 29.489 36.954 30.029 ;
     RECT  2.415 29.875 21.51 30.065 ;
     RECT  38.088 29.903 38.682 30.065 ;
     RECT  38.088 30.065 38.106 30.101 ;
     RECT  20.844 30.065 21.51 30.136 ;
     RECT  22.248 29.831 24.93 30.136 ;
     RECT  25.704 29.875 27.882 30.145 ;
     RECT  25.704 30.145 28.17 30.271 ;
     RECT  28.944 30.029 35.982 30.271 ;
     RECT  25.704 30.271 35.982 30.299 ;
     RECT  2.415 30.065 20.034 30.407 ;
     RECT  36.936 30.029 36.954 30.443 ;
     RECT  25.704 30.299 30.618 30.479 ;
     RECT  2.415 30.407 19.926 30.611 ;
     RECT  2.415 30.611 19.746 30.713 ;
     RECT  25.704 30.479 28.314 30.721 ;
     RECT  2.415 30.713 19.638 30.749 ;
     RECT  18.252 30.749 19.638 30.839 ;
     RECT  2.415 30.749 17.406 30.859 ;
     RECT  20.844 30.136 24.93 30.955 ;
     RECT  25.668 30.721 28.314 30.955 ;
     RECT  2.412 30.859 17.406 30.983 ;
     RECT  20.844 30.955 28.314 30.991 ;
     RECT  18.252 30.839 19.602 31.253 ;
     RECT  20.736 30.991 28.314 31.253 ;
     RECT  20.736 31.253 24.426 31.339 ;
     RECT  25.344 31.253 28.314 31.339 ;
     RECT  29.088 30.479 30.618 31.339 ;
     RECT  25.344 31.339 30.618 31.373 ;
     RECT  25.344 31.373 25.794 31.379 ;
     RECT  26.748 31.373 30.618 31.531 ;
     RECT  31.428 30.299 35.946 31.531 ;
     RECT  25.452 31.379 25.794 31.559 ;
     RECT  2.415 30.983 17.406 31.649 ;
     RECT  18.252 31.253 19.458 31.649 ;
     RECT  25.524 31.559 25.794 31.649 ;
     RECT  26.748 31.531 35.946 31.649 ;
     RECT  2.415 31.649 14.778 31.685 ;
     RECT  20.484 31.339 24.426 31.685 ;
     RECT  26.748 31.649 35.514 31.685 ;
     RECT  3.6 31.685 14.778 31.721 ;
     RECT  15.732 31.649 17.19 31.721 ;
     RECT  18.615 31.649 19.458 31.721 ;
     RECT  22.536 31.685 24.426 31.721 ;
     RECT  22.536 31.721 22.554 31.757 ;
     RECT  20.484 31.685 21.726 31.793 ;
     RECT  23.292 31.721 24.426 31.793 ;
     RECT  25.524 31.649 25.758 31.805 ;
     RECT  3.6 31.721 3.618 31.829 ;
     RECT  23.4 31.793 24.426 31.829 ;
     RECT  26.748 31.685 35.097 31.829 ;
     RECT  4.536 31.721 14.778 31.919 ;
     RECT  15.804 31.721 17.19 31.919 ;
     RECT  20.556 31.793 21.69 31.919 ;
     RECT  23.4 31.829 24.297 31.919 ;
     RECT  25.524 31.805 25.542 31.919 ;
     RECT  26.748 31.829 28.458 31.919 ;
     RECT  29.268 31.829 30.186 31.919 ;
     RECT  31.572 31.829 35.097 31.919 ;
     RECT  29.304 31.919 29.697 31.949 ;
     RECT  26.82 31.919 27.63 31.955 ;
     RECT  28.44 31.919 28.458 31.955 ;
     RECT  31.572 31.919 32.346 31.955 ;
     RECT  33.732 31.919 33.75 31.955 ;
     RECT  16.092 31.919 17.19 31.991 ;
     RECT  20.556 31.919 21.51 31.991 ;
     RECT  23.508 31.919 24.297 31.991 ;
     RECT  27.612 31.955 27.63 31.991 ;
     RECT  31.572 31.955 31.59 31.997 ;
     RECT  32.328 31.955 32.346 31.997 ;
     RECT  26.82 31.955 26.838 32.063 ;
     RECT  20.556 31.991 20.574 32.099 ;
     RECT  21.492 31.991 21.51 32.099 ;
     RECT  36.468 31.801 36.486 32.099 ;
     RECT  2.415 31.685 2.697 32.147 ;
     RECT  18.615 31.721 18.897 32.147 ;
     RECT  24.015 31.991 24.297 32.147 ;
     RECT  29.415 31.949 29.697 32.147 ;
     RECT  34.815 31.919 35.097 32.147 ;
     RECT  40.215 28.787 40.497 32.147 ;
     RECT  4.536 31.919 13.734 32.189 ;
     RECT  4.536 32.189 4.554 32.195 ;
     RECT  5.292 32.189 6.822 32.225 ;
     RECT  16.344 31.991 17.19 32.225 ;
     RECT  16.524 32.225 17.19 32.261 ;
     RECT  7.815 32.189 13.734 32.297 ;
     RECT  14.76 31.919 14.778 32.297 ;
     RECT  6.228 32.225 6.498 32.369 ;
     RECT  9 32.297 13.734 32.369 ;
     RECT  16.524 32.261 16.542 32.369 ;
     RECT  2.415 32.147 2.505 32.417 ;
     RECT  7.815 32.297 8.226 32.417 ;
     RECT  12.924 32.369 13.305 32.417 ;
     RECT  18.615 32.147 18.705 32.417 ;
     RECT  24.015 32.147 24.105 32.417 ;
     RECT  29.415 32.147 29.505 32.417 ;
     RECT  34.815 32.147 34.905 32.417 ;
     RECT  40.215 32.147 40.305 32.417 ;
     RECT  5.472 32.225 5.49 32.459 ;
     RECT  6.228 32.369 6.246 32.459 ;
     RECT  8.208 32.417 8.226 32.459 ;
     RECT  9 32.369 12.006 32.459 ;
     RECT  12.924 32.417 12.942 32.459 ;
     RECT  9 32.459 11.826 33.647 ;
     RECT  9 33.647 11.538 33.677 ;
     RECT  9 33.677 11.502 33.683 ;
     RECT  9 33.683 11.466 34.428 ;
    LAYER M4 ;
     RECT  0.156 14.88 0.181 15.192 ;
     RECT  0.181 14.88 0.227 16.104 ;
     RECT  0.227 15.024 0.245 16.104 ;
     RECT  2.401 10.176 2.408 10.2 ;
     RECT  0.245 15.168 2.408 16.104 ;
     RECT  2.401 28.464 2.408 28.488 ;
     RECT  2.401 30.864 2.408 30.888 ;
     RECT  2.408 2.148 2.512 32.412 ;
     RECT  2.512 2.418 2.704 32.142 ;
     RECT  2.704 28.464 2.873 29.496 ;
     RECT  2.704 30.864 2.915 31.368 ;
     RECT  2.704 18.432 3.117 19.368 ;
     RECT  2.704 9.504 3.305 12.552 ;
     RECT  2.704 3.408 3.395 4.344 ;
     RECT  2.704 14.208 3.443 16.584 ;
     RECT  3.305 11.376 3.485 12.552 ;
     RECT  3.733 7.44 3.781 7.464 ;
     RECT  2.915 30.912 3.845 31.368 ;
     RECT  3.781 7.44 3.868 7.896 ;
     RECT  3.868 7.44 3.875 7.464 ;
     RECT  3.443 14.208 3.913 16.104 ;
     RECT  3.829 5.664 3.917 5.688 ;
     RECT  2.704 22.176 3.949 22.2 ;
     RECT  3.949 22.176 3.95 22.248 ;
     RECT  2.704 24.528 3.985 24.552 ;
     RECT  3.841 27.888 3.985 27.912 ;
     RECT  2.873 29.04 4.025 29.496 ;
     RECT  3.395 3.408 4.061 3.432 ;
     RECT  2.704 23.28 4.205 23.304 ;
     RECT  3.485 12.096 4.277 12.552 ;
     RECT  3.845 30.912 4.549 30.936 ;
     RECT  3.985 27.216 4.741 27.912 ;
     RECT  4.025 29.472 4.741 29.496 ;
     RECT  4.549 30.576 4.741 30.936 ;
     RECT  3.985 24.528 4.777 25.464 ;
     RECT  4.741 29.472 4.835 30.936 ;
     RECT  3.117 19.344 4.892 19.368 ;
     RECT  4.892 18.768 4.979 19.368 ;
     RECT  3.913 13.92 5.125 16.104 ;
     RECT  4.561 17.088 5.125 17.112 ;
     RECT  5.125 13.92 5.141 17.112 ;
     RECT  4.979 19.344 5.141 19.368 ;
     RECT  5.141 16.08 5.171 17.112 ;
     RECT  4.835 29.472 5.249 29.688 ;
     RECT  4.835 30.912 5.285 30.936 ;
     RECT  4.777 24.48 5.353 25.464 ;
     RECT  2.704 21.12 5.389 21.144 ;
     RECT  4.741 27.216 5.393 28.44 ;
     RECT  4.957 11.424 5.465 11.448 ;
     RECT  5.353 23.904 5.468 25.464 ;
     RECT  5.468 23.904 5.509 25.656 ;
     RECT  5.509 23.904 5.537 25.992 ;
     RECT  5.537 25.632 5.555 25.992 ;
     RECT  3.305 9.504 5.789 10.392 ;
     RECT  5.141 13.92 5.789 14.904 ;
     RECT  5.389 20.832 5.789 21.144 ;
     RECT  4.273 6.72 5.857 6.744 ;
     RECT  4.525 32.16 5.933 32.184 ;
     RECT  5.537 23.904 6.005 24.552 ;
     RECT  4.777 4.656 6.073 4.68 ;
     RECT  3.95 22.224 6.145 22.248 ;
     RECT  6.085 30.528 6.172 30.552 ;
     RECT  5.171 16.08 6.277 17.016 ;
     RECT  5.713 18.096 6.277 18.12 ;
     RECT  5.789 10.368 6.293 10.392 ;
     RECT  5.393 27.36 6.329 28.44 ;
     RECT  5.749 7.872 6.361 7.896 ;
     RECT  6.277 16.08 6.428 17.064 ;
     RECT  6.073 4.656 6.469 5.592 ;
     RECT  6.428 15.984 6.469 17.064 ;
     RECT  6.277 18.096 6.469 18.84 ;
     RECT  5.789 20.832 6.545 20.856 ;
     RECT  6.469 4.464 6.572 5.592 ;
     RECT  5.857 6.672 6.572 6.744 ;
     RECT  6.613 2.88 6.649 2.904 ;
     RECT  6.572 4.464 6.649 6.744 ;
     RECT  5.555 25.968 6.757 25.992 ;
     RECT  6.757 25.68 6.829 25.992 ;
     RECT  5.249 29.472 6.829 29.496 ;
     RECT  6.829 29.472 6.833 30.456 ;
     RECT  6.757 23.808 7.117 23.832 ;
     RECT  6.649 2.88 7.261 6.744 ;
     RECT  6.361 7.872 7.261 8.568 ;
     RECT  6.469 15.984 7.261 18.84 ;
     RECT  6.329 27.36 7.261 27.96 ;
     RECT  7.261 2.88 7.292 8.808 ;
     RECT  6.145 22.224 7.477 22.488 ;
     RECT  6.793 13.632 7.549 13.656 ;
     RECT  5.789 14.88 7.549 14.904 ;
     RECT  6.613 11.376 7.58 11.4 ;
     RECT  6.833 30.384 7.585 30.456 ;
     RECT  7.369 31.68 7.585 31.704 ;
     RECT  7.117 23.808 7.669 24.12 ;
     RECT  6.829 25.104 7.669 25.992 ;
     RECT  7.585 30.384 7.729 31.704 ;
     RECT  7.292 2.688 7.808 8.808 ;
     RECT  7.58 10.464 7.808 11.4 ;
     RECT  6.001 12.384 7.808 12.408 ;
     RECT  7.549 13.632 7.808 14.904 ;
     RECT  7.261 15.984 7.808 19.56 ;
     RECT  7.477 22.224 7.808 22.776 ;
     RECT  7.669 23.808 7.808 25.992 ;
     RECT  7.261 27.168 7.808 27.96 ;
     RECT  7.549 28.992 7.808 29.016 ;
     RECT  7.729 30.384 7.808 31.944 ;
     RECT  7.808 2.148 7.912 32.412 ;
     RECT  7.912 2.256 8.104 32.142 ;
     RECT  8.104 19.536 8.165 19.56 ;
     RECT  8.104 22.224 8.243 31.992 ;
     RECT  8.243 22.752 8.291 31.992 ;
     RECT  8.104 13.104 8.309 14.52 ;
     RECT  8.291 23.904 8.339 31.992 ;
     RECT  8.104 2.256 8.425 9.816 ;
     RECT  8.309 13.632 8.453 14.52 ;
     RECT  8.453 14.496 8.597 14.52 ;
     RECT  8.339 24.48 9.029 31.992 ;
     RECT  8.104 15.984 9.097 16.824 ;
     RECT  8.104 17.904 9.097 17.928 ;
     RECT  8.104 20.592 9.097 21.144 ;
     RECT  9.097 20.592 9.101 21.672 ;
     RECT  8.449 0.528 9.125 0.552 ;
     RECT  9.029 24.48 9.137 29.592 ;
     RECT  9.029 30.768 9.169 31.992 ;
     RECT  9.125 0.528 9.209 0.6 ;
     RECT  8.104 10.848 9.281 12.024 ;
     RECT  9.097 15.984 9.349 17.928 ;
     RECT  8.425 2.784 9.421 9.816 ;
     RECT  9.209 0.528 9.491 0.552 ;
     RECT  9.169 30.768 9.491 32.472 ;
     RECT  9.421 2.304 9.589 9.816 ;
     RECT  9.137 24.48 9.637 29.4 ;
     RECT  9.589 2.304 9.673 9.864 ;
     RECT  9.101 21.648 9.701 21.672 ;
     RECT  8.291 22.752 9.701 22.872 ;
     RECT  9.013 33.648 9.701 33.672 ;
     RECT  9.701 21.648 9.785 22.872 ;
     RECT  9.637 24.144 9.785 29.4 ;
     RECT  9.701 33.024 9.785 33.672 ;
     RECT  9.349 15.408 9.893 17.928 ;
     RECT  9.673 2.256 9.922 9.864 ;
     RECT  9.922 2.208 9.98 9.864 ;
     RECT  9.281 10.848 9.98 11.256 ;
     RECT  9.785 22.848 10.141 22.872 ;
     RECT  9.785 24.96 10.141 29.4 ;
     RECT  10.141 22.848 10.165 23.16 ;
     RECT  10.141 24.96 10.213 29.688 ;
     RECT  9.491 30.768 10.213 32.04 ;
     RECT  9.893 15.408 10.289 17.64 ;
     RECT  10.289 15.408 10.361 16.536 ;
     RECT  10.361 15.408 10.397 16.2 ;
     RECT  9.98 2.208 10.453 11.256 ;
     RECT  9.101 20.592 10.465 20.616 ;
     RECT  10.261 12.528 10.549 12.552 ;
     RECT  10.549 12.528 10.649 12.6 ;
     RECT  10.165 22.848 10.753 23.928 ;
     RECT  10.213 24.96 10.753 32.04 ;
     RECT  10.681 0.576 10.786 0.6 ;
     RECT  10.786 0.528 10.787 0.6 ;
     RECT  10.649 12.576 10.793 12.6 ;
     RECT  9.785 33.648 10.885 33.672 ;
     RECT  10.885 33.024 11.027 33.672 ;
     RECT  10.753 22.848 11.029 32.04 ;
     RECT  11.077 13.584 11.185 13.8 ;
     RECT  9.785 21.648 11.221 21.672 ;
     RECT  11.029 22.848 11.221 32.472 ;
     RECT  11.221 21.648 11.261 32.472 ;
     RECT  11.261 21.648 11.369 32.04 ;
     RECT  10.453 1.728 11.401 11.256 ;
     RECT  10.465 20.544 11.401 20.616 ;
     RECT  11.369 21.648 11.401 31.464 ;
     RECT  11.185 12.72 11.413 14.328 ;
     RECT  10.397 16.08 11.413 16.2 ;
     RECT  10.289 17.616 11.441 17.64 ;
     RECT  11.401 20.544 11.485 31.464 ;
     RECT  11.027 33.648 11.549 33.672 ;
     RECT  11.413 12.72 11.581 15.048 ;
     RECT  11.413 16.08 11.581 16.344 ;
     RECT  11.485 21.6 11.585 31.464 ;
     RECT  10.787 0.528 11.621 0.552 ;
     RECT  11.585 23.952 11.729 31.464 ;
     RECT  11.401 1.728 11.797 11.448 ;
     RECT  11.581 12.72 11.797 16.344 ;
     RECT  11.485 20.544 11.941 20.616 ;
     RECT  11.797 1.728 11.987 16.344 ;
     RECT  11.941 19.872 11.987 20.616 ;
     RECT  11.585 21.6 11.987 22.824 ;
     RECT  11.987 22.224 11.989 22.824 ;
     RECT  12.013 0.288 12.037 0.312 ;
     RECT  11.989 22.224 12.053 22.728 ;
     RECT  12.037 0.192 12.611 0.312 ;
     RECT  11.729 24.096 12.985 31.464 ;
     RECT  11.987 1.728 13.208 14.328 ;
     RECT  11.987 15.408 13.208 16.344 ;
     RECT  12.188 17.52 13.208 17.544 ;
     RECT  12.229 18.768 13.208 18.792 ;
     RECT  11.987 19.872 13.208 20.568 ;
     RECT  12.053 22.224 13.208 22.248 ;
     RECT  12.985 24.096 13.208 31.704 ;
     RECT  13.208 1.728 13.312 32.412 ;
     RECT  13.312 1.728 13.385 32.142 ;
     RECT  13.385 1.776 13.457 32.142 ;
     RECT  13.457 2.256 13.504 32.142 ;
     RECT  12.611 0.192 13.667 0.216 ;
     RECT  13.504 24.096 13.673 31.704 ;
     RECT  13.504 22.224 13.781 22.776 ;
     RECT  13.673 24.096 13.781 31.464 ;
     RECT  13.781 22.224 13.889 22.248 ;
     RECT  13.504 4.512 14.033 13.608 ;
     RECT  14.033 9.696 14.141 13.608 ;
     RECT  14.033 5.664 14.221 8.616 ;
     RECT  13.781 31.392 14.249 31.464 ;
     RECT  14.141 12.528 14.393 13.608 ;
     RECT  13.504 15.84 14.573 16.584 ;
     RECT  13.504 2.256 14.605 3.432 ;
     RECT  14.033 4.512 14.605 4.536 ;
     RECT  14.221 5.664 14.609 8.52 ;
     RECT  14.605 2.256 14.645 4.536 ;
     RECT  13.781 24.096 14.689 30.216 ;
     RECT  14.689 24.096 14.713 28.968 ;
     RECT  14.689 30.192 14.717 30.216 ;
     RECT  14.713 23.856 14.819 28.968 ;
     RECT  14.393 12.528 14.933 12.648 ;
     RECT  14.573 15.84 15.001 16.344 ;
     RECT  14.141 9.696 15.005 10.968 ;
     RECT  14.609 5.664 15.109 8.28 ;
     RECT  15.005 9.696 15.155 9.816 ;
     RECT  15.109 5.088 15.193 8.28 ;
     RECT  13.504 18.768 15.205 20.52 ;
     RECT  15.205 18.768 15.221 20.568 ;
     RECT  14.933 12.528 15.289 12.552 ;
     RECT  15.221 19.344 15.292 20.568 ;
     RECT  15.193 5.664 15.293 8.28 ;
     RECT  14.819 23.904 15.329 28.968 ;
     RECT  15.005 10.848 15.349 10.968 ;
     RECT  15.289 11.952 15.349 12.552 ;
     RECT  15.349 10.848 15.395 12.552 ;
     RECT  15.293 5.664 15.401 5.976 ;
     RECT  15.155 9.792 15.437 9.816 ;
     RECT  15.395 10.944 15.437 12.552 ;
     RECT  14.645 2.256 15.473 3.576 ;
     RECT  15.292 19.344 15.617 20.04 ;
     RECT  15.329 23.904 15.653 28.872 ;
     RECT  14.677 13.968 15.761 13.992 ;
     RECT  15.617 19.344 15.761 19.368 ;
     RECT  15.293 7.392 15.905 8.28 ;
     RECT  15.001 15.36 15.925 16.344 ;
     RECT  15.925 14.784 15.971 16.344 ;
     RECT  15.653 25.152 15.971 28.872 ;
     RECT  15.905 7.392 16.06 7.8 ;
     RECT  15.971 14.784 16.085 14.808 ;
     RECT  15.109 21.648 16.121 21.672 ;
     RECT  15.401 5.664 16.225 5.832 ;
     RECT  14.249 31.392 16.225 31.416 ;
     RECT  15.653 23.904 16.265 23.928 ;
     RECT  15.971 25.152 16.301 25.752 ;
     RECT  15.473 2.688 16.405 3.576 ;
     RECT  16.225 31.392 16.441 31.944 ;
     RECT  15.437 10.944 16.513 11.976 ;
     RECT  16.441 30.768 16.547 31.944 ;
     RECT  16.405 2.688 16.661 3.96 ;
     RECT  16.301 25.152 16.697 25.608 ;
     RECT  16.697 25.152 16.837 25.512 ;
     RECT  15.971 15.84 17.053 16.344 ;
     RECT  16.333 17.952 17.053 17.976 ;
     RECT  16.06 7.776 17.089 7.8 ;
     RECT  16.837 25.104 17.089 25.512 ;
     RECT  17.089 7.2 17.129 7.8 ;
     RECT  15.971 27.024 17.129 28.872 ;
     RECT  16.661 3.024 17.197 3.96 ;
     RECT  16.225 5.568 17.197 5.832 ;
     RECT  17.197 3.024 17.237 5.832 ;
     RECT  17.18 8.928 17.267 8.952 ;
     RECT  16.513 10.848 17.269 11.976 ;
     RECT  17.269 10.608 17.377 11.976 ;
     RECT  17.377 10.608 17.417 12.648 ;
     RECT  17.053 15.84 17.449 17.976 ;
     RECT  17.417 10.608 17.459 11.16 ;
     RECT  17.129 27.312 17.489 28.872 ;
     RECT  17.521 13.824 17.557 13.848 ;
     RECT  17.237 4.656 17.633 5.832 ;
     RECT  16.837 23.232 17.653 23.256 ;
     RECT  17.653 22.752 17.701 23.784 ;
     RECT  17.089 25.056 17.701 25.512 ;
     RECT  16.547 31.344 17.809 31.416 ;
     RECT  17.701 22.752 18.025 25.512 ;
     RECT  17.633 5.808 18.349 5.832 ;
     RECT  17.129 7.2 18.349 7.224 ;
     RECT  17.953 9.216 18.469 9.24 ;
     RECT  17.489 27.312 18.469 28.68 ;
     RECT  17.459 11.136 18.565 11.16 ;
     RECT  18.349 5.808 18.601 7.224 ;
     RECT  17.557 13.824 18.601 14.28 ;
     RECT  17.237 3.024 18.608 3.576 ;
     RECT  17.633 4.656 18.608 4.68 ;
     RECT  18.601 5.808 18.608 7.752 ;
     RECT  18.469 9.072 18.608 9.24 ;
     RECT  18.565 10.896 18.608 11.16 ;
     RECT  17.417 12.528 18.608 12.648 ;
     RECT  18.601 13.824 18.608 14.424 ;
     RECT  17.449 15.552 18.608 18.216 ;
     RECT  18.025 22.752 18.608 26.184 ;
     RECT  18.469 27.312 18.608 28.968 ;
     RECT  17.809 30.432 18.608 31.416 ;
     RECT  18.608 2.148 18.712 32.412 ;
     RECT  18.712 2.352 18.904 32.142 ;
     RECT  18.904 12.528 19.253 16.344 ;
     RECT  19.253 15.024 19.289 16.344 ;
     RECT  18.904 19.536 19.361 20.472 ;
     RECT  18.904 10.896 19.397 11.4 ;
     RECT  18.904 5.472 19.469 6.696 ;
     RECT  18.904 2.352 19.613 2.568 ;
     RECT  18.904 7.728 19.613 7.752 ;
     RECT  19.361 20.448 19.613 20.472 ;
     RECT  19.289 15.024 19.721 15.048 ;
     RECT  18.904 22.944 19.811 23.928 ;
     RECT  18.904 27.456 19.897 27.912 ;
     RECT  18.904 28.944 19.897 28.968 ;
     RECT  18.904 9.072 19.907 9.72 ;
     RECT  18.904 17.616 19.933 17.976 ;
     RECT  19.897 26.832 19.937 28.968 ;
     RECT  18.904 30.144 19.937 30.6 ;
     RECT  19.397 11.376 19.955 11.4 ;
     RECT  19.253 12.528 19.955 13.608 ;
     RECT  19.933 25.392 19.969 25.416 ;
     RECT  19.969 25.392 20.041 25.8 ;
     RECT  19.937 26.832 20.041 28.488 ;
     RECT  19.289 16.08 20.077 16.344 ;
     RECT  19.933 17.616 20.077 18.024 ;
     RECT  20.041 25.392 20.117 28.488 ;
     RECT  20.117 25.392 20.153 27.48 ;
     RECT  20.153 25.392 20.185 27.432 ;
     RECT  20.117 28.464 20.189 28.488 ;
     RECT  18.904 4.224 20.221 4.248 ;
     RECT  20.221 3.936 20.261 4.248 ;
     RECT  19.469 5.472 20.261 5.832 ;
     RECT  19.955 12.72 20.369 13.608 ;
     RECT  20.261 3.936 20.401 3.96 ;
     RECT  19.613 2.352 20.585 2.376 ;
     RECT  20.185 25.296 20.585 27.432 ;
     RECT  20.401 3.408 20.621 3.96 ;
     RECT  20.077 16.08 20.693 18.024 ;
     RECT  19.811 23.904 20.761 23.928 ;
     RECT  20.473 31.344 20.761 31.368 ;
     RECT  20.585 25.776 20.765 27.432 ;
     RECT  20.545 7.632 20.833 7.656 ;
     RECT  20.761 23.904 20.833 24.264 ;
     RECT  20.833 7.632 20.873 8.52 ;
     RECT  20.693 16.08 20.909 16.344 ;
     RECT  20.693 17.328 20.977 18.024 ;
     RECT  20.873 8.112 21.017 8.52 ;
     RECT  18.904 21.792 21.017 21.816 ;
     RECT  20.369 13.584 21.053 13.608 ;
     RECT  21.049 15.024 21.068 15.048 ;
     RECT  21.017 8.208 21.125 8.52 ;
     RECT  21.068 14.304 21.155 15.048 ;
     RECT  20.977 17.328 21.155 18.696 ;
     RECT  19.937 30.144 21.193 30.168 ;
     RECT  21.049 6.816 21.197 6.84 ;
     RECT  21.125 8.448 21.233 8.52 ;
     RECT  21.155 17.328 21.233 17.352 ;
     RECT  20.261 5.808 21.265 5.832 ;
     RECT  21.193 30.144 21.265 30.36 ;
     RECT  20.761 31.344 21.265 31.656 ;
     RECT  21.265 30.144 21.409 31.656 ;
     RECT  19.907 9.696 21.625 9.72 ;
     RECT  21.373 4.224 21.629 4.248 ;
     RECT  21.109 11.136 21.661 11.16 ;
     RECT  21.155 18.672 21.665 18.696 ;
     RECT  20.833 23.28 21.733 24.264 ;
     RECT  20.765 25.776 21.733 26.856 ;
     RECT  21.265 5.712 21.773 5.832 ;
     RECT  21.155 14.784 21.779 15.048 ;
     RECT  21.409 30.144 21.809 31.8 ;
     RECT  21.625 9.504 21.973 9.72 ;
     RECT  21.973 9.504 22.019 10.056 ;
     RECT  21.233 8.448 22.06 8.472 ;
     RECT  20.977 28.56 22.093 28.584 ;
     RECT  22.019 10.032 22.259 10.056 ;
     RECT  20.653 19.968 22.273 19.992 ;
     RECT  22.057 21.792 22.273 21.816 ;
     RECT  22.273 19.968 22.274 20.04 ;
     RECT  21.779 15.024 22.313 15.048 ;
     RECT  22.273 21.792 22.381 21.96 ;
     RECT  21.733 23.28 22.381 26.856 ;
     RECT  22.381 21.792 22.499 26.856 ;
     RECT  21.661 11.136 22.597 11.976 ;
     RECT  22.597 10.896 22.669 11.976 ;
     RECT  22.165 13.056 22.669 13.08 ;
     RECT  22.499 21.792 22.691 23.304 ;
     RECT  22.691 21.792 22.709 22.824 ;
     RECT  22.709 21.936 22.732 22.824 ;
     RECT  22.597 17.616 22.741 17.64 ;
     RECT  22.741 17.616 22.787 18.408 ;
     RECT  22.705 6.912 22.789 6.936 ;
     RECT  22.093 28.272 22.849 28.584 ;
     RECT  22.849 28.272 22.889 28.824 ;
     RECT  22.129 4.848 23.065 5.64 ;
     RECT  21.809 30.336 23.245 31.8 ;
     RECT  22.889 28.8 23.425 28.824 ;
     RECT  23.245 30.048 23.425 31.8 ;
     RECT  22.499 24.624 23.461 26.856 ;
     RECT  23.497 7.728 23.569 7.752 ;
     RECT  22.274 20.016 23.569 20.04 ;
     RECT  23.065 4.464 23.749 5.64 ;
     RECT  22.237 2.592 23.785 2.616 ;
     RECT  23.785 2.496 23.857 2.616 ;
     RECT  23.749 3.696 23.857 5.64 ;
     RECT  23.569 6.672 23.857 6.696 ;
     RECT  23.857 2.304 24.001 2.616 ;
     RECT  23.569 7.728 24.001 8.184 ;
     RECT  24.001 2.256 24.008 2.616 ;
     RECT  23.857 3.696 24.008 6.696 ;
     RECT  24.001 7.68 24.008 8.184 ;
     RECT  23.641 9.6 24.008 9.624 ;
     RECT  22.669 10.896 24.008 13.08 ;
     RECT  20.909 16.32 24.008 16.344 ;
     RECT  22.787 18.24 24.008 18.408 ;
     RECT  23.569 20.016 24.008 20.184 ;
     RECT  22.732 21.936 24.008 22.488 ;
     RECT  23.461 24.624 24.008 27.096 ;
     RECT  23.425 28.8 24.008 31.8 ;
     RECT  24.008 2.148 24.112 32.412 ;
     RECT  24.112 2.256 24.304 32.142 ;
     RECT  24.304 2.256 24.419 7.992 ;
     RECT  24.304 8.976 24.473 10.152 ;
     RECT  24.419 2.304 24.509 7.752 ;
     RECT  24.473 9.6 24.509 10.152 ;
     RECT  24.304 17.616 24.545 18.264 ;
     RECT  24.304 23.904 24.563 27.096 ;
     RECT  24.509 2.304 24.581 7.224 ;
     RECT  24.581 2.304 24.611 5.832 ;
     RECT  24.509 10.128 24.653 10.152 ;
     RECT  24.304 19.776 24.689 20.184 ;
     RECT  24.611 2.304 24.725 2.52 ;
     RECT  24.563 23.904 24.869 27 ;
     RECT  24.304 28.8 24.905 31.8 ;
     RECT  24.611 3.696 24.941 5.832 ;
     RECT  24.905 28.8 24.941 29.304 ;
     RECT  24.725 2.496 25.049 2.52 ;
     RECT  24.941 4.656 25.069 5.832 ;
     RECT  24.304 21.936 25.104 22.2 ;
     RECT  24.941 28.8 25.121 28.824 ;
     RECT  24.869 23.904 25.297 24.648 ;
     RECT  25.104 21.936 25.477 21.96 ;
     RECT  25.069 4.656 25.517 5.784 ;
     RECT  24.869 25.92 25.523 27 ;
     RECT  24.304 16.32 25.553 16.536 ;
     RECT  25.297 22.992 25.589 24.648 ;
     RECT  24.905 30.336 25.769 31.8 ;
     RECT  24.545 17.616 25.837 17.64 ;
     RECT  25.517 5.76 25.877 5.784 ;
     RECT  24.689 19.776 25.877 19.8 ;
     RECT  25.523 26.784 25.877 27 ;
     RECT  25.621 3.264 25.981 3.432 ;
     RECT  24.304 11.136 26.125 11.16 ;
     RECT  25.589 22.992 26.129 23.928 ;
     RECT  25.837 17.616 26.149 18.216 ;
     RECT  26.129 22.992 26.273 23.064 ;
     RECT  25.477 21.504 26.449 21.96 ;
     RECT  25.981 3.264 26.633 3.48 ;
     RECT  26.633 3.264 26.665 3.432 ;
     RECT  25.873 9.264 26.684 9.288 ;
     RECT  26.125 10.848 26.684 11.16 ;
     RECT  26.684 9.264 26.725 11.16 ;
     RECT  26.593 24.624 26.737 24.648 ;
     RECT  25.769 30.336 26.737 31.704 ;
     RECT  24.581 7.2 26.771 7.224 ;
     RECT  26.449 20.544 26.773 21.96 ;
     RECT  26.273 22.992 26.773 23.016 ;
     RECT  26.149 17.616 26.813 18.792 ;
     RECT  26.665 3.072 26.849 3.432 ;
     RECT  26.737 30.336 26.885 31.896 ;
     RECT  26.725 8.976 26.957 11.16 ;
     RECT  26.849 3.072 27.065 3.288 ;
     RECT  26.773 20.544 27.137 23.016 ;
     RECT  25.553 16.32 27.205 16.344 ;
     RECT  26.813 17.616 27.205 17.64 ;
     RECT  27.205 16.32 27.245 17.64 ;
     RECT  24.304 13.536 27.313 13.56 ;
     RECT  27.245 16.32 27.313 17.112 ;
     RECT  27.313 15.648 27.421 17.112 ;
     RECT  26.125 28.464 27.425 29.304 ;
     RECT  27.065 3.072 27.497 3.096 ;
     RECT  25.877 26.784 27.641 26.808 ;
     RECT  26.885 30.336 27.641 31.704 ;
     RECT  27.313 13.536 27.673 13.608 ;
     RECT  27.421 15.456 27.731 17.112 ;
     RECT  27.673 13.536 27.757 14.232 ;
     RECT  27.137 21.12 27.877 23.016 ;
     RECT  27.877 21.12 27.964 23.4 ;
     RECT  26.737 24.624 28.001 25.176 ;
     RECT  27.964 22.992 28.109 23.4 ;
     RECT  25.517 4.656 28.165 4.728 ;
     RECT  27.529 6 28.165 6.024 ;
     RECT  28.165 4.656 28.211 6.024 ;
     RECT  26.957 10.32 28.211 11.16 ;
     RECT  28.133 12.528 28.217 12.552 ;
     RECT  27.641 30.816 28.429 31.704 ;
     RECT  27.757 13.536 28.717 13.848 ;
     RECT  27.425 29.232 28.717 29.304 ;
     RECT  28.897 2.976 28.969 3 ;
     RECT  27.964 21.12 28.969 21.96 ;
     RECT  28.109 22.992 28.969 23.16 ;
     RECT  28.211 5.472 29.041 6.024 ;
     RECT  28.981 26.256 29.041 26.28 ;
     RECT  28.001 24.624 29.113 24.648 ;
     RECT  29.041 26.256 29.113 26.856 ;
     RECT  27.731 15.456 29.149 15.48 ;
     RECT  27.731 17.088 29.293 17.112 ;
     RECT  29.113 24.624 29.329 26.856 ;
     RECT  28.429 30.816 29.365 31.944 ;
     RECT  28.969 2.976 29.408 3.048 ;
     RECT  29.041 5.472 29.408 6.216 ;
     RECT  26.957 8.976 29.408 9 ;
     RECT  28.211 10.32 29.408 10.344 ;
     RECT  28.321 12.048 29.408 12.072 ;
     RECT  28.717 13.392 29.408 13.848 ;
     RECT  29.149 15.456 29.408 15.768 ;
     RECT  29.293 17.088 29.408 17.496 ;
     RECT  26.813 18.768 29.408 18.792 ;
     RECT  28.969 21.12 29.408 23.16 ;
     RECT  29.329 24.624 29.408 27.192 ;
     RECT  28.717 29.04 29.408 29.304 ;
     RECT  29.365 30.432 29.408 31.944 ;
     RECT  29.408 2.148 29.512 32.412 ;
     RECT  29.512 2.418 29.704 32.142 ;
     RECT  29.704 5.472 29.939 6.024 ;
     RECT  29.704 7.344 29.98 7.608 ;
     RECT  29.704 26.256 30.197 27.192 ;
     RECT  29.704 21.408 30.233 22.488 ;
     RECT  30.233 21.408 30.515 22.248 ;
     RECT  29.704 17.088 30.521 17.64 ;
     RECT  29.704 28.8 30.665 31.8 ;
     RECT  29.704 19.824 30.737 20.328 ;
     RECT  30.665 29.04 30.755 31.8 ;
     RECT  30.521 17.616 30.805 17.64 ;
     RECT  29.704 18.768 30.805 18.792 ;
     RECT  29.704 15.408 30.841 15.768 ;
     RECT  30.755 29.04 30.917 29.64 ;
     RECT  30.841 15.408 30.953 15.96 ;
     RECT  30.917 29.232 30.953 29.64 ;
     RECT  30.805 17.616 31.093 18.792 ;
     RECT  30.737 19.824 31.093 20.088 ;
     RECT  31.085 23.376 31.169 23.4 ;
     RECT  29.704 10.32 31.237 10.344 ;
     RECT  31.093 17.616 31.277 20.088 ;
     RECT  29.98 7.344 31.417 7.368 ;
     RECT  31.277 17.616 31.421 19.176 ;
     RECT  30.515 21.504 31.453 22.248 ;
     RECT  31.417 7.056 31.457 7.368 ;
     RECT  31.421 17.616 31.493 18.696 ;
     RECT  29.704 13.296 31.529 13.992 ;
     RECT  30.755 31.296 31.561 31.8 ;
     RECT  29.939 5.472 31.597 5.496 ;
     RECT  31.529 13.296 31.601 13.848 ;
     RECT  31.493 17.664 31.601 18.696 ;
     RECT  31.237 10.32 31.637 11.256 ;
     RECT  31.597 5.472 31.916 5.736 ;
     RECT  31.916 5.424 31.957 5.736 ;
     RECT  31.457 7.056 31.957 7.08 ;
     RECT  31.957 5.424 32.003 7.08 ;
     RECT  30.197 26.256 32.065 26.28 ;
     RECT  29.704 3.024 32.141 3.048 ;
     RECT  32.065 26.256 32.177 26.856 ;
     RECT  31.993 20.16 32.249 20.184 ;
     RECT  31.453 21.504 32.317 23.016 ;
     RECT  31.561 31.296 32.357 31.992 ;
     RECT  32.317 21.504 32.573 23.064 ;
     RECT  32.573 22.992 32.677 23.064 ;
     RECT  31.601 18.192 32.681 18.696 ;
     RECT  32.177 26.256 32.681 26.616 ;
     RECT  32.003 5.472 32.717 7.08 ;
     RECT  31.637 10.32 33.037 10.872 ;
     RECT  32.681 18.672 33.109 18.696 ;
     RECT  31.601 13.296 33.149 13.8 ;
     RECT  32.857 17.088 33.149 17.112 ;
     RECT  33.109 18.672 33.149 18.792 ;
     RECT  32.677 22.992 33.289 23.304 ;
     RECT  33.149 13.296 33.397 13.656 ;
     RECT  30.953 15.456 33.469 15.96 ;
     RECT  33.037 10.128 33.577 10.872 ;
     RECT  33.149 18.768 33.613 18.792 ;
     RECT  32.357 31.296 33.721 31.32 ;
     RECT  33.577 10.128 33.757 11.832 ;
     RECT  33.397 12.864 33.757 13.656 ;
     RECT  33.289 22.992 33.793 23.88 ;
     RECT  33.757 10.128 33.797 13.656 ;
     RECT  33.613 18.768 33.829 19.272 ;
     RECT  32.681 26.256 34.045 26.28 ;
     RECT  30.953 29.28 34.124 29.64 ;
     RECT  33.721 30.816 34.124 31.32 ;
     RECT  33.797 11.808 34.153 13.656 ;
     RECT  32.573 21.504 34.153 21.672 ;
     RECT  34.045 25.872 34.165 26.28 ;
     RECT  34.153 21.312 34.477 21.672 ;
     RECT  33.469 15.408 34.513 15.96 ;
     RECT  34.477 21.216 34.549 21.672 ;
     RECT  34.513 15.264 34.585 15.96 ;
     RECT  34.124 29.28 34.693 31.32 ;
     RECT  34.549 21.072 34.729 21.672 ;
     RECT  34.693 28.464 34.765 31.32 ;
     RECT  34.333 2.352 34.808 2.376 ;
     RECT  32.717 5.472 34.808 6.168 ;
     RECT  33.797 10.128 34.808 10.392 ;
     RECT  34.153 11.808 34.808 13.704 ;
     RECT  34.585 15.216 34.808 15.96 ;
     RECT  34.693 17.664 34.808 17.688 ;
     RECT  33.829 18.768 34.808 19.368 ;
     RECT  34.729 20.592 34.808 21.672 ;
     RECT  33.793 22.896 34.808 23.88 ;
     RECT  34.165 25.872 34.808 27.096 ;
     RECT  34.765 28.464 34.808 31.416 ;
     RECT  34.808 2.148 34.912 32.412 ;
     RECT  34.912 2.352 35.104 32.142 ;
     RECT  35.104 26.112 35.219 27.432 ;
     RECT  35.104 9.312 35.237 10.344 ;
     RECT  35.104 13.152 35.237 13.704 ;
     RECT  35.104 20.592 35.237 23.352 ;
     RECT  35.237 13.536 35.309 13.704 ;
     RECT  35.104 28.416 35.309 31.416 ;
     RECT  35.219 26.112 35.315 27.096 ;
     RECT  35.104 24.48 35.381 24.648 ;
     RECT  35.309 28.464 35.453 31.416 ;
     RECT  35.309 13.536 35.489 13.656 ;
     RECT  35.453 29.28 35.525 31.416 ;
     RECT  35.104 17.136 35.561 18.792 ;
     RECT  35.237 21.504 35.669 23.352 ;
     RECT  35.669 23.328 35.705 23.352 ;
     RECT  35.525 29.28 35.741 30.456 ;
     RECT  35.741 29.328 35.813 30.456 ;
     RECT  35.104 2.352 35.957 2.376 ;
     RECT  35.489 13.536 35.957 13.608 ;
     RECT  35.104 4.944 35.993 5.496 ;
     RECT  35.237 9.312 36.029 9.336 ;
     RECT  35.381 24.48 36.101 24.6 ;
     RECT  35.315 26.256 36.137 27.096 ;
     RECT  35.669 21.504 36.209 22.2 ;
     RECT  35.237 10.32 36.349 10.344 ;
     RECT  35.813 29.328 36.425 29.544 ;
     RECT  36.421 12.528 36.529 12.552 ;
     RECT  35.957 13.536 36.529 13.56 ;
     RECT  35.561 17.136 36.533 17.16 ;
     RECT  35.561 18.144 36.605 18.792 ;
     RECT  36.349 10.32 36.641 10.872 ;
     RECT  36.529 12.528 36.641 13.56 ;
     RECT  35.104 15.216 36.709 15.768 ;
     RECT  35.993 5.472 36.755 5.496 ;
     RECT  36.641 13.2 36.893 13.56 ;
     RECT  36.709 4.272 36.929 4.296 ;
     RECT  36.893 13.248 36.965 13.56 ;
     RECT  36.425 29.52 36.965 29.544 ;
     RECT  36.817 20.976 37.037 21.096 ;
     RECT  36.641 10.32 37.073 10.344 ;
     RECT  36.965 13.296 37.109 13.32 ;
     RECT  36.605 18.24 37.292 18.792 ;
     RECT  37.292 18.24 37.379 19.464 ;
     RECT  36.709 14.832 37.505 15.768 ;
     RECT  36.277 2.208 37.573 2.232 ;
     RECT  37.465 3.696 37.573 3.72 ;
     RECT  37.573 2.208 37.619 3.72 ;
     RECT  36.101 24.48 37.649 24.504 ;
     RECT  37.037 20.976 37.685 21 ;
     RECT  37.379 18.24 37.897 18.744 ;
     RECT  37.505 14.832 37.933 15.528 ;
     RECT  37.897 18.048 37.937 18.744 ;
     RECT  36.209 22.176 37.957 22.2 ;
     RECT  37.619 2.784 38.009 3.72 ;
     RECT  37.933 23.952 38.017 23.976 ;
     RECT  37.957 22.176 38.045 22.824 ;
     RECT  38.041 29.376 38.113 29.4 ;
     RECT  38.108 6.48 38.149 6.504 ;
     RECT  38.149 5.664 38.195 6.504 ;
     RECT  37.933 14.064 38.195 15.528 ;
     RECT  37.861 19.776 38.333 19.8 ;
     RECT  38.009 3.696 38.405 3.72 ;
     RECT  38.045 22.8 38.405 22.824 ;
     RECT  38.195 14.88 38.545 15.528 ;
     RECT  38.077 11.472 38.581 11.496 ;
     RECT  38.195 5.664 38.657 5.688 ;
     RECT  38.545 14.88 38.657 15.816 ;
     RECT  38.113 28.464 38.689 29.4 ;
     RECT  38.581 11.472 38.765 11.784 ;
     RECT  38.765 11.472 38.801 11.496 ;
     RECT  38.653 13.872 38.801 13.896 ;
     RECT  38.657 14.88 38.801 15.528 ;
     RECT  37.861 17.04 38.837 17.064 ;
     RECT  37.937 18.048 38.837 18.072 ;
     RECT  38.689 28.464 39.017 29.448 ;
     RECT  38.473 23.904 39.161 23.928 ;
     RECT  39.017 29.376 39.161 29.448 ;
     RECT  39.161 29.424 39.233 29.448 ;
     RECT  38.797 19.344 39.409 19.368 ;
     RECT  38.905 26.736 39.625 26.76 ;
     RECT  38.977 9.696 40.208 9.72 ;
     RECT  39.265 14.784 40.208 14.808 ;
     RECT  39.409 19.344 40.208 19.992 ;
     RECT  39.329 22.224 40.208 22.248 ;
     RECT  39.625 26.736 40.208 26.856 ;
     RECT  40.208 2.148 40.312 32.412 ;
     RECT  40.312 2.418 40.504 32.142 ;
    LAYER M5 ;
     RECT  9.024 0.144 13.512 0.181 ;
     RECT  9.024 0.181 13.656 0.563 ;
     RECT  9.168 0.563 13.656 0.611 ;
     RECT  2.4 2.137 2.52 2.151 ;
     RECT  7.8 2.137 7.92 2.151 ;
     RECT  18.6 2.137 18.72 2.151 ;
     RECT  24 2.137 24.12 2.151 ;
     RECT  29.4 2.137 29.52 2.151 ;
     RECT  34.8 2.137 34.92 2.151 ;
     RECT  40.2 2.137 40.32 2.151 ;
     RECT  7.8 2.151 8.112 2.245 ;
     RECT  9.312 0.611 13.656 2.245 ;
     RECT  24 2.151 24.312 2.245 ;
     RECT  7.8 2.245 13.656 2.677 ;
     RECT  24 2.245 24.408 2.725 ;
     RECT  7.344 2.677 13.656 2.821 ;
     RECT  7.344 2.821 13.992 3.107 ;
     RECT  2.4 2.151 2.712 3.397 ;
     RECT  7.68 3.107 13.992 3.443 ;
     RECT  37.584 2.197 37.608 3.731 ;
     RECT  24 2.725 24.6 4.019 ;
     RECT  2.4 3.397 3.384 4.355 ;
     RECT  7.68 3.443 13.656 5.077 ;
     RECT  22.464 4.837 22.488 5.605 ;
     RECT  22.464 5.605 22.776 5.651 ;
     RECT  7.008 5.077 13.656 5.653 ;
     RECT  29.4 2.151 29.712 5.989 ;
     RECT  7.008 5.653 14.04 6.229 ;
     RECT  31.968 3.013 31.992 6.515 ;
     RECT  6.624 6.229 14.04 6.707 ;
     RECT  7.008 6.707 14.04 6.709 ;
     RECT  15.12 5.077 15.144 6.709 ;
     RECT  22.752 5.651 22.776 6.947 ;
     RECT  24 4.019 24.312 7.045 ;
     RECT  7.008 6.709 15.144 7.381 ;
     RECT  3.84 5.653 3.864 7.475 ;
     RECT  29.4 5.989 29.928 7.619 ;
     RECT  7.008 7.381 16.008 7.811 ;
     RECT  7.008 7.811 15.144 7.955 ;
     RECT  24 7.045 24.408 8.003 ;
     RECT  7.632 7.955 15.144 8.771 ;
     RECT  18.6 2.151 18.912 9.061 ;
     RECT  18.48 9.061 19.896 9.251 ;
     RECT  24 8.003 24.312 9.349 ;
     RECT  3.792 7.861 3.816 9.731 ;
     RECT  12.24 8.771 15.144 9.731 ;
     RECT  18.6 9.251 19.896 9.731 ;
     RECT  24 9.349 24.408 9.971 ;
     RECT  21.984 8.437 22.008 10.021 ;
     RECT  21.984 10.021 22.248 10.067 ;
     RECT  2.4 4.355 2.712 10.165 ;
     RECT  7.632 8.771 11.256 10.165 ;
     RECT  12.24 9.731 14.376 10.165 ;
     RECT  7.632 10.165 14.376 10.355 ;
     RECT  17.232 3.541 17.256 10.597 ;
     RECT  17.232 10.597 17.448 10.883 ;
     RECT  26.736 7.189 26.76 10.883 ;
     RECT  7.632 10.355 13.608 11.075 ;
     RECT  9.12 11.075 13.608 11.171 ;
     RECT  17.424 10.883 17.448 11.171 ;
     RECT  2.4 10.165 3.288 11.365 ;
     RECT  7.632 11.075 8.112 11.365 ;
     RECT  22.224 10.067 22.248 11.459 ;
     RECT  15.36 10.837 15.384 11.939 ;
     RECT  9.12 11.171 9.144 12.035 ;
     RECT  2.4 11.365 3.432 12.563 ;
     RECT  10.272 11.171 13.608 12.563 ;
     RECT  28.176 4.645 28.2 12.563 ;
     RECT  10.56 12.563 13.608 12.611 ;
     RECT  11.088 12.611 13.608 13.139 ;
     RECT  19.92 11.365 19.944 13.139 ;
     RECT  11.088 13.139 13.512 13.811 ;
     RECT  21.12 11.125 21.144 14.773 ;
     RECT  36.72 4.261 36.744 14.867 ;
     RECT  38.16 5.653 38.184 14.915 ;
     RECT  11.712 13.811 13.512 15.013 ;
     RECT  21.12 14.773 21.768 15.059 ;
     RECT  15.936 14.773 15.96 15.395 ;
     RECT  17.568 15.685 17.592 15.827 ;
     RECT  2.4 12.563 2.712 15.829 ;
     RECT  7.44 11.365 8.112 15.973 ;
     RECT  6.48 15.973 8.112 16.019 ;
     RECT  11.424 15.013 13.512 16.019 ;
     RECT  0.192 14.869 0.216 16.115 ;
     RECT  11.424 16.019 11.928 16.115 ;
     RECT  27.696 14.197 27.72 16.309 ;
     RECT  27.6 16.309 27.72 16.355 ;
     RECT  2.4 15.829 3.432 16.595 ;
     RECT  6.48 16.019 6.504 17.027 ;
     RECT  5.136 16.981 5.16 17.123 ;
     RECT  11.424 16.115 11.448 17.509 ;
     RECT  13.2 16.019 13.512 17.509 ;
     RECT  21.12 15.059 21.144 17.987 ;
     RECT  22.752 17.605 22.776 18.419 ;
     RECT  2.4 16.595 2.712 18.421 ;
     RECT  7.8 16.019 8.112 18.757 ;
     RECT  11.424 17.509 13.512 18.803 ;
     RECT  6.288 17.029 6.312 18.851 ;
     RECT  40.2 2.151 40.512 19.333 ;
     RECT  2.4 18.421 3.048 19.379 ;
     RECT  37.344 18.229 37.368 19.475 ;
     RECT  7.68 18.757 8.112 19.571 ;
     RECT  11.424 18.803 11.448 19.861 ;
     RECT  14.976 18.757 15 20.005 ;
     RECT  14.976 20.005 15.24 20.051 ;
     RECT  15.216 20.051 15.24 20.579 ;
     RECT  7.8 19.571 8.112 20.581 ;
     RECT  11.424 19.861 11.976 21.251 ;
     RECT  29.4 7.619 29.712 21.397 ;
     RECT  31.104 18.565 31.128 21.397 ;
     RECT  29.4 21.397 31.128 21.539 ;
     RECT  27.6 16.355 27.624 21.683 ;
     RECT  18.6 9.731 18.912 21.781 ;
     RECT  29.4 21.539 29.712 21.925 ;
     RECT  26.16 18.181 26.184 21.971 ;
     RECT  24 9.971 24.312 22.165 ;
     RECT  4.944 18.757 4.968 22.259 ;
     RECT  39.36 19.333 40.512 22.259 ;
     RECT  7.8 20.581 8.232 22.741 ;
     RECT  13.2 18.803 13.512 22.741 ;
     RECT  18.6 21.781 19.8 22.741 ;
     RECT  22.464 21.925 22.488 22.789 ;
     RECT  11.952 21.251 11.976 22.835 ;
     RECT  7.68 22.741 8.712 22.883 ;
     RECT  9.744 22.165 9.768 22.883 ;
     RECT  17.664 22.741 19.8 22.979 ;
     RECT  27.888 21.925 29.712 23.171 ;
     RECT  10.848 23.173 10.872 23.221 ;
     RECT  22.464 22.789 22.68 23.315 ;
     RECT  10.176 23.221 10.872 23.317 ;
     RECT  27.888 23.171 27.912 23.411 ;
     RECT  31.104 21.539 31.128 23.411 ;
     RECT  17.664 22.979 18.912 23.795 ;
     RECT  7.68 22.883 8.28 23.845 ;
     RECT  7.632 23.845 8.28 23.893 ;
     RECT  24 22.165 25.032 23.893 ;
     RECT  37.968 22.789 37.992 23.987 ;
     RECT  24 23.893 25.128 24.613 ;
     RECT  13.2 22.741 13.656 24.659 ;
     RECT  14.784 23.845 14.808 24.805 ;
     RECT  13.2 24.659 13.512 24.901 ;
     RECT  10.176 23.317 11.208 24.997 ;
     RECT  7.632 23.893 8.328 25.045 ;
     RECT  9.504 24.997 11.208 25.045 ;
     RECT  14.496 24.805 14.808 25.141 ;
     RECT  7.632 25.045 11.208 25.283 ;
     RECT  16.992 25.141 17.016 25.331 ;
     RECT  5.088 24.469 5.112 25.475 ;
     RECT  7.68 25.283 11.208 25.621 ;
     RECT  13.104 24.901 13.512 25.621 ;
     RECT  7.68 25.621 13.512 25.715 ;
     RECT  7.8 25.715 13.512 25.813 ;
     RECT  14.496 25.141 15.096 25.813 ;
     RECT  34.8 2.151 35.112 25.861 ;
     RECT  24 24.613 25.512 25.955 ;
     RECT  5.52 25.621 5.544 26.003 ;
     RECT  34.176 25.861 35.112 26.101 ;
     RECT  18.6 23.795 18.912 26.149 ;
     RECT  22.464 23.315 22.488 26.243 ;
     RECT  28.992 23.171 29.712 26.291 ;
     RECT  7.8 25.813 15.096 26.531 ;
     RECT  13.104 26.531 15.096 26.629 ;
     RECT  13.104 26.629 15.96 26.819 ;
     RECT  24 25.955 24.552 27.107 ;
     RECT  18.24 26.149 18.912 27.347 ;
     RECT  5.712 27.349 5.736 27.877 ;
     RECT  13.2 26.819 14.52 27.877 ;
     RECT  5.712 27.877 6.12 27.923 ;
     RECT  15.936 26.819 15.96 27.971 ;
     RECT  13.2 27.877 14.664 27.973 ;
     RECT  7.8 26.531 11.4 28.405 ;
     RECT  18.48 27.347 18.912 28.979 ;
     RECT  7.8 28.405 11.832 29.077 ;
     RECT  13.104 27.973 14.664 29.077 ;
     RECT  2.4 19.379 2.712 29.365 ;
     RECT  7.8 29.077 14.664 29.507 ;
     RECT  34.176 26.101 35.304 29.651 ;
     RECT  13.056 29.507 14.664 29.699 ;
     RECT  7.8 29.507 11.448 29.891 ;
     RECT  13.056 29.699 13.848 30.227 ;
     RECT  27.36 28.453 27.384 30.371 ;
     RECT  7.8 29.891 11.4 30.373 ;
     RECT  30.72 29.173 30.744 30.467 ;
     RECT  6.096 27.923 6.12 30.563 ;
     RECT  4.8 29.461 4.824 30.565 ;
     RECT  4.56 30.565 4.824 30.611 ;
     RECT  7.68 30.373 11.4 30.803 ;
     RECT  29.232 26.291 29.712 30.851 ;
     RECT  2.4 29.365 2.904 30.899 ;
     RECT  4.56 30.611 4.584 30.947 ;
     RECT  22.8 30.901 22.824 31.043 ;
     RECT  34.176 29.651 35.112 31.091 ;
     RECT  13.056 30.227 13.608 31.331 ;
     RECT  7.68 30.803 11.352 31.379 ;
     RECT  7.68 31.379 8.112 31.427 ;
     RECT  13.056 31.331 13.512 31.523 ;
     RECT  26.784 31.429 26.808 31.571 ;
     RECT  29.28 30.851 29.712 31.811 ;
     RECT  16.512 30.757 16.536 31.955 ;
     RECT  31.872 31.285 31.896 31.955 ;
     RECT  9.312 31.379 11.352 32.003 ;
     RECT  2.4 30.899 2.712 32.409 ;
     RECT  7.8 31.427 8.112 32.409 ;
     RECT  13.2 31.523 13.512 32.409 ;
     RECT  18.6 28.979 18.912 32.409 ;
     RECT  24 27.107 24.312 32.409 ;
     RECT  29.4 31.811 29.712 32.409 ;
     RECT  34.8 31.091 35.112 32.409 ;
     RECT  40.2 22.259 40.512 32.409 ;
     RECT  2.4 32.409 2.52 32.423 ;
     RECT  7.8 32.409 7.92 32.423 ;
     RECT  13.2 32.409 13.32 32.423 ;
     RECT  18.6 32.409 18.72 32.423 ;
     RECT  24 32.409 24.12 32.423 ;
     RECT  29.4 32.409 29.52 32.423 ;
     RECT  34.8 32.409 34.92 32.423 ;
     RECT  40.2 32.409 40.32 32.423 ;
     RECT  9.312 32.003 11.208 33.637 ;
     RECT  9.024 33.637 11.208 34.384 ;
     RECT  9.168 0.611 9.312 2.137 ;
     RECT  7.92 2.137 9.312 2.151 ;
     RECT  8.112 2.151 9.312 2.245 ;
     RECT  17.256 3.541 18.6 9.061 ;
     RECT  2.712 4.355 3.384 5.653 ;
     RECT  28.2 4.645 29.4 12.563 ;
     RECT  22.488 4.837 24 5.605 ;
     RECT  13.656 5.077 15.12 5.653 ;
     RECT  22.776 5.605 24 6.947 ;
     RECT  2.712 5.653 3.84 7.475 ;
     RECT  14.04 5.653 15.12 6.709 ;
     RECT  36.744 5.653 38.16 14.867 ;
     RECT  26.76 7.189 28.176 10.883 ;
     RECT  16.008 7.381 17.232 7.811 ;
     RECT  2.712 7.475 3.816 7.861 ;
     RECT  2.712 7.861 3.792 9.731 ;
     RECT  24.312 8.003 24.408 9.349 ;
     RECT  11.256 8.771 12.24 10.165 ;
     RECT  17.256 9.061 18.48 9.251 ;
     RECT  17.256 9.251 18.6 10.597 ;
     RECT  2.712 9.731 3.288 10.165 ;
     RECT  21.984 10.067 22.224 11.125 ;
     RECT  17.448 10.597 18.6 11.171 ;
     RECT  8.112 11.075 9.12 12.035 ;
     RECT  21.144 11.125 22.224 11.459 ;
     RECT  9.144 11.171 10.272 12.035 ;
     RECT  18.912 11.365 19.92 13.139 ;
     RECT  19.944 11.365 21.12 13.139 ;
     RECT  11.424 13.811 11.712 15.013 ;
     RECT  17.592 15.685 18.6 15.827 ;
     RECT  6.504 16.019 7.8 17.027 ;
     RECT  11.928 16.019 13.2 16.115 ;
     RECT  11.448 16.115 13.2 17.509 ;
     RECT  5.16 16.981 6.48 17.027 ;
     RECT  5.16 17.027 7.8 17.029 ;
     RECT  5.16 17.029 6.288 17.123 ;
     RECT  6.312 17.029 7.8 18.757 ;
     RECT  22.776 17.605 24 18.419 ;
     RECT  26.184 18.181 27.6 21.683 ;
     RECT  29.712 18.565 31.104 21.397 ;
     RECT  4.968 18.757 6.288 18.851 ;
     RECT  6.312 18.757 7.68 18.851 ;
     RECT  13.512 18.757 14.976 20.051 ;
     RECT  11.448 18.803 13.2 19.861 ;
     RECT  11.976 19.861 13.2 22.835 ;
     RECT  29.712 21.539 31.104 23.411 ;
     RECT  22.488 21.925 24 22.789 ;
     RECT  8.232 22.165 9.744 22.741 ;
     RECT  8.712 22.741 9.744 22.883 ;
     RECT  22.68 22.789 24 23.315 ;
     RECT  8.28 22.883 8.328 23.893 ;
     RECT  27.912 23.171 28.992 23.411 ;
     RECT  22.488 23.315 24 26.243 ;
     RECT  13.656 23.845 14.784 24.659 ;
     RECT  13.512 24.659 14.784 24.805 ;
     RECT  13.512 24.805 14.496 25.813 ;
     RECT  8.328 24.997 9.504 25.045 ;
     RECT  13.104 26.819 13.2 27.973 ;
     RECT  14.52 26.819 15.936 27.877 ;
     RECT  14.664 27.877 15.936 27.971 ;
     RECT  11.832 28.405 13.104 29.077 ;
     RECT  29.712 29.173 30.72 30.467 ;
     RECT  4.824 29.461 6.096 30.563 ;
     RECT  22.824 30.901 24 31.043 ;
     RECT  8.112 31.379 9.312 32.409 ;
     RECT  7.92 32.409 9.312 32.423 ;
     RECT  9.024 32.423 9.312 33.637 ;
  END
END ot_s81_markov_pair_native
END LIBRARY
